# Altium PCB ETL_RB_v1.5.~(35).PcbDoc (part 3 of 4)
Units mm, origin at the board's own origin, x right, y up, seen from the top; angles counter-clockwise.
Board outline 130.3 x 56.5 mm, 8 copper layers (Top Layer, plane 1, M1, plane 2, plane 3, M2, plane 4, Bottom Layer), stack 0.937 mm thick; 212 components, 186 nets, 1961 pads, 953 vias.
Unrouted connection lines stored in the file: 395.

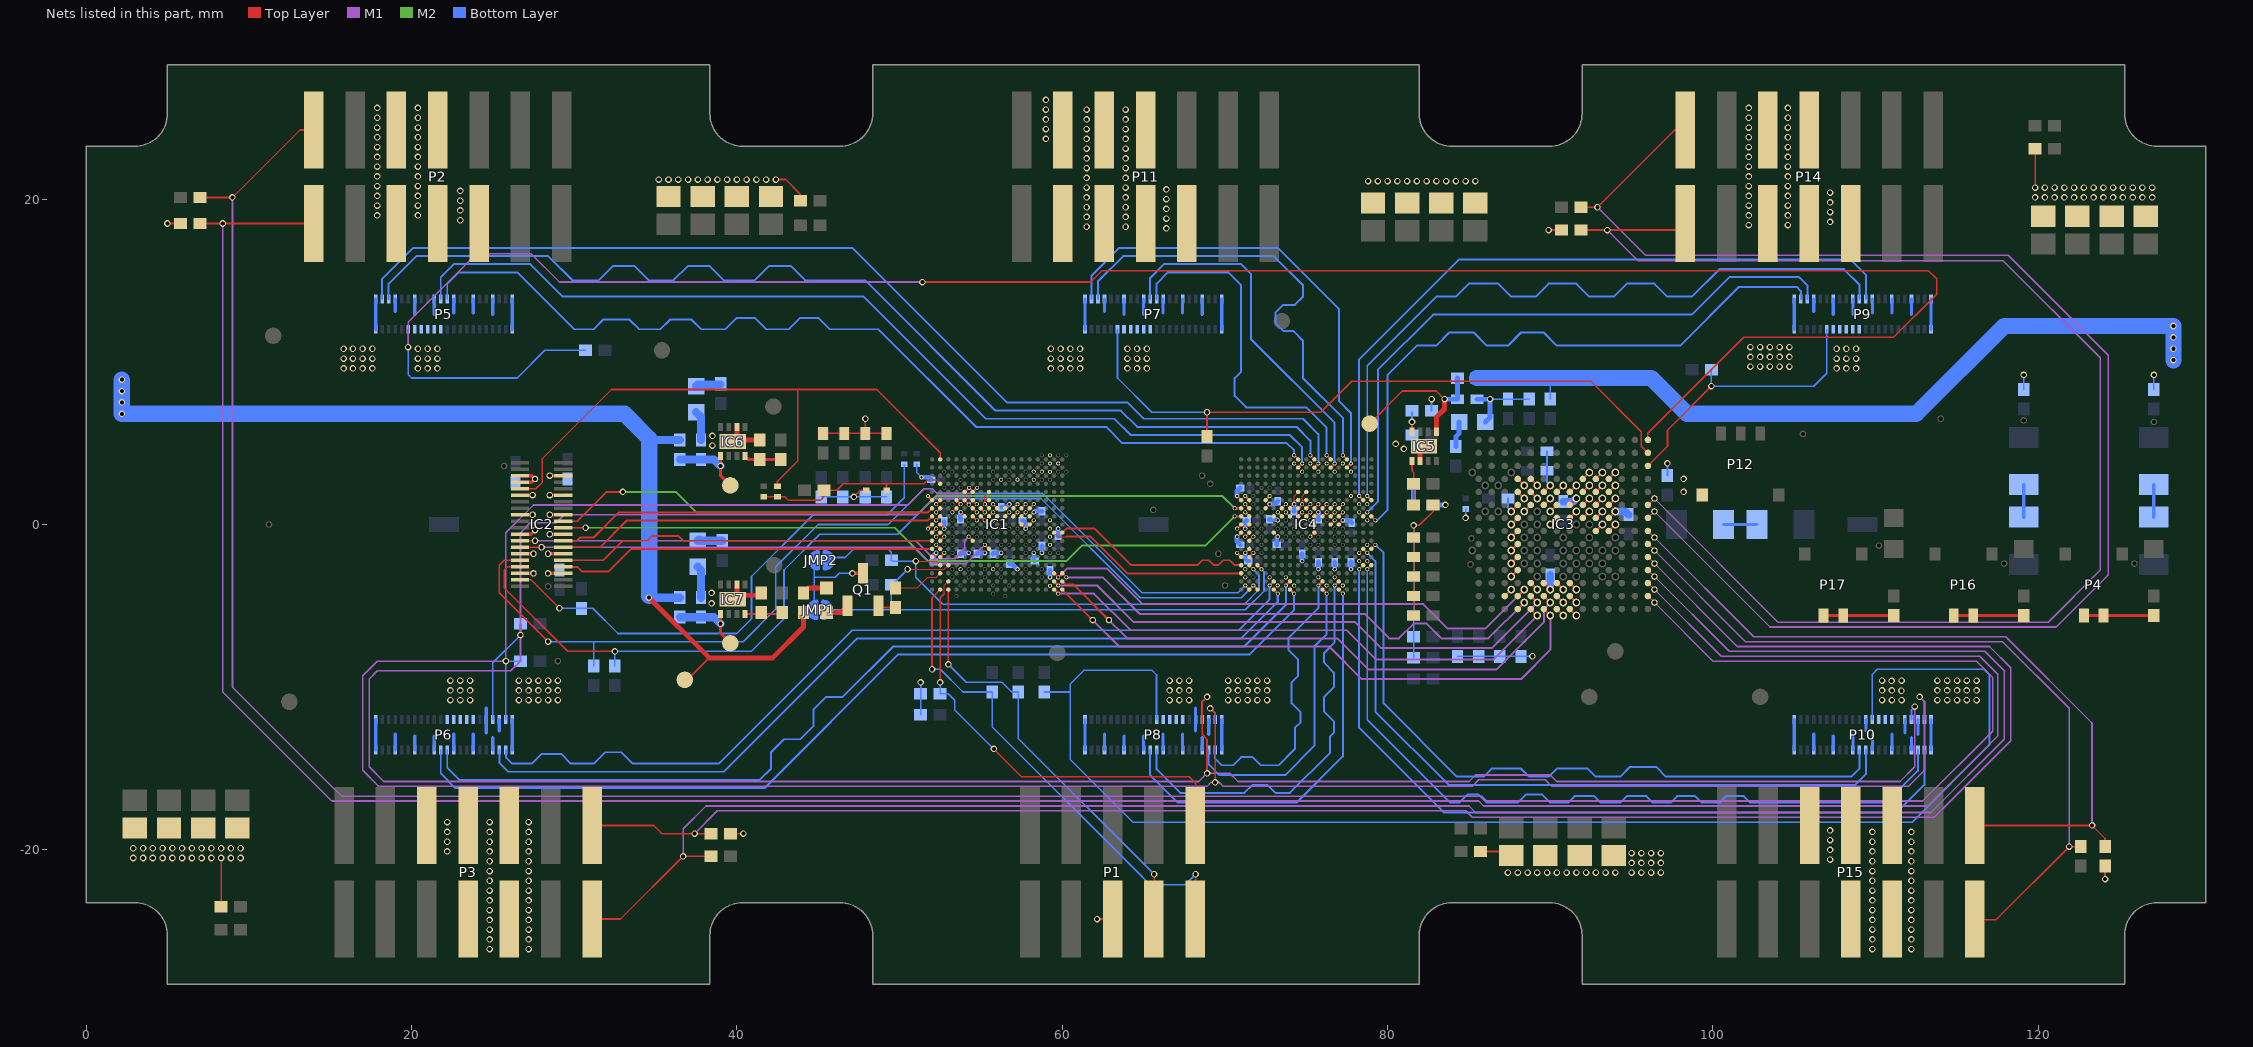
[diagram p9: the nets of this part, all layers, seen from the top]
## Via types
v1: diameter 0.4, hole 0.25, Top Layer to Bottom Layer, 953 vias

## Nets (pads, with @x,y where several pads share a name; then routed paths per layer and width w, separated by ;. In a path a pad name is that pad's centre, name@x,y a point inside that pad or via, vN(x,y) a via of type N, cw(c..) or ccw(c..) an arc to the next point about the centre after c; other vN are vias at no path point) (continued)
GND: C105.2 C106.2 C107.2 C108.2 C109.2 C111.2 C112.2 C113.2 C114.2 C115.2 C116.2 C117.2 C118.2 C119.2 C120.2 C121.2 C122.2 C123.2 C124.2 C125.2 C126.2 C127.2 C128.2 C129.2 C130.2 C131.2 C132.2 C133.2 C134.2 C135.2 C136.2 C138.2 C139.2 C140.2 C141.2 C150.2 C151.2 C152.2 C153.2 C154.2 C155.2 C160.2 C162.2 C163.2 C164.2 C165.2 C166.2 C167.2 C168.2 C169.2 C201.1 C202.1 C203.1 C204.1 C205.1 C206.1 C207.1 C208.1 C209.1 C210.1 C211.1 C212.1 C213.1 C214.1 C218.2 C219.2 C220.2 C221.2 C222.2 C223.2 C224.2 C225.2 C226.2 C227.2 C228.2 C229.2 C230.2 C231.2 C232.2 C233.2 IC1.E8 IC1.F1 IC1.F2 IC1.F4 IC1.F8 IC1.G2 IC1.G4 IC1.G6 IC1.G7 IC1.G8 IC1.G9 IC1.G10 IC1.G11 IC1.G12 IC1.G13 IC1.H2 IC1.H5 IC1.H6 IC1.H7 IC1.H8 IC1.H9 IC1.H10 IC1.H11 IC1.H12 IC1.H13 IC1.J1 IC1.J2 IC1.J12 IC1.J13 IC1.K1 IC1.K2 IC1.L2 IC1.M2 IC1.N1 IC1.N2 IC2.5 IC2.6 IC2.11 IC2.12 IC2.17 IC2.18 IC2.23 IC2.24 IC2.29 IC2.30 IC2.34 IC2.35 IC2.36 IC3.D4 IC3.D5 IC3.D6 IC3.D7 IC3.D8 IC3.E4 IC3.E5 IC3.E6 IC3.E7 IC3.E8 IC3.F4 IC3.F5 IC3.F6 IC3.F7 IC3.G5 IC3.G6 IC3.G7 IC3.G12 IC3.G13 IC3.G14 IC3.H5 IC3.H6 IC3.H7 IC3.H12 IC3.H13 IC3.H14 IC3.J5 IC3.J6 IC3.J12 IC3.K4 IC3.K5 IC3.K6 IC3.K12 IC3.L4 IC3.L5 IC3.L6 IC3.L7 IC3.L8 IC3.L9 IC3.L10 IC3.L11 IC3.M13 IC4.E8 IC4.E9 IC4.F1 IC4.F2 IC4.F4 IC4.F8 IC4.F9 IC4.G2 IC4.G4 IC4.G6 IC4.G7 IC4.G8 IC4.G9 IC4.G10 IC4.G11 IC4.G12 IC4.G13 IC4.H2 IC4.H5 IC4.H6 IC4.H7 IC4.H8 IC4.H9 IC4.H10 IC4.H11 IC4.H12 IC4.H13 IC4.J1 IC4.J2 IC4.J10 IC4.J12 IC4.J13 IC4.K1 IC4.K2 IC4.K5 IC4.K10 IC4.L2 IC4.M2 IC4.N1 IC4.N2 IC5.6 IC5.9 IC6.6 IC6.9 IC7.6 IC7.9 JMP1.1 JMP2.1 P1.6 P2.5 P2.6 P2.7 P2.8 P2.9 P3.5 P3.6 P3.7 P3.8 P3.9 P5.11 P5.12 P5.13 P5.14 P5.15 P5.23 P5.26 P5.29 P5.32 P5.35 P5.38 P5.41 P5.42 P5.43 P5.44 P6.11 P6.12 P6.13 P6.14 P6.15 P6.17 P6.19 P6.23 P6.26 P6.29 P6.32 P6.35 P6.38 P6.41 P6.42 P6.43 P6.44 P7.11 P7.12 P7.13 P7.14 P7.15 P7.23 P7.26 P7.29 P7.32 P7.35 P7.38 P7.41 P7.42 P7.43 P7.44 P8.12 P8.13 P8.14 P8.15 P8.17 P8.19 P8.23 P8.26 P8.29 P8.32 P8.35 P8.38 P8.41 P8.42 P8.43 P8.44 P9.11 P9.12 P9.13 P9.14 P9.15 P9.23 P9.26 P9.29 P9.32 P9.35 P9.38 P9.41 P9.42 P9.43 P9.44 P10.11 P10.13 P10.14 P10.15 P10.17 P10.19 P10.23 P10.26 P10.29 P10.32 P10.35 P10.38 P10.41 P10.42 P10.43 P10.44 P11.5 P11.6 P11.7 P11.8 P11.9 P12.4 P14.5 P14.6 P14.7 P14.8 P14.9 P15.5 P15.6 P15.7 P15.8 P15.9 pad.1@27.5,-1.8 pad.1@27.5,-3 pad.1@27.6,2.8 pad.1@27.6,-0.35 pad.1@27.45,0.6 pad.1@27.45,1.8 pad.1@28.4,-1.8 pad.1@28.4,-3 pad.1@28.5,0.6 pad.1@28.5,1.8 pad.1@28.5,3 pad.1@28.5,-0.6 pad.1@51.35,2.9 pad.1@51.75,1.75 pad.1@51.75,-0.25 pad.1@52.25,0.25 pad.1@52.25,0.75 pad.1@52.25,1.25 pad.1@52.25,-0.25 pad.1@52.25,-0.75 pad.1@52.25,-1.25 pad.1@52.25,-1.75 pad.1@52.75,-0.25 pad.1@52.75,-0.75 pad.1@52.75,-1.75 pad.1@53.25,0.75 pad.1@53.75,0.75 pad.1@53.75,1.25 pad.1@53.75,-2.75 pad.1@54.25,-1.75 pad.1@54.75,0.25 pad.1@54.75,0.75 pad.1@55.25,0.25 pad.1@55.25,0.75 pad.1@55.25,1.25 pad.1@55.25,-1.75 pad.1@55.75,0.25 pad.1@55.75,0.75 pad.1@55.75,1.25 pad.1@55.75,-2.75 pad.1@56.25,2.75 pad.1@56.25,-1.75 pad.1@56.75,0.75 pad.1@56.75,1.25 pad.1@57.25,0.75 pad.1@57.25,1.25 pad.1@57.25,2.75 pad.1@57.25,-2.75 pad.1@57.75,0.75 pad.1@57.75,1.25 pad.1@57.75,-0.25 pad.1@58.25,0.25 pad.1@58.25,0.75 pad.1@58.25,1.25 pad.1@58.25,2.75 pad.1@58.25,3.25 pad.1@58.25,-1.75 pad.1@58.75,3.25 pad.1@58.75,-1.75 pad.1@59.25,0.25 pad.1@59.25,3.75 pad.1@59.25,4.25 pad.1@59.25,-0.25 pad.1@59.25,-0.75 pad.1@59.25,-1.25 pad.1@59.25,-3.25 pad.1@59.75,3.75 pad.1@59.75,-0.25 pad.1@59.248,3.238 pad.1@59.248,-3.771 pad.1@70.75,1.75 pad.1@70.75,-0.25 pad.1@70.75,-0.75 pad.1@70.75,-1.75 pad.1@71.25,0.75 pad.1@71.25,1.25 pad.1@71.25,1.75 pad.1@71.25,-0.25 pad.1@71.25,-0.75 pad.1@71.25,-1.75 pad.1@71.25,-2.75 pad.1@71.25,-3.25 pad.1@71.75,-0.75 pad.1@71.75,-1.75 pad.1@72.75,1.25 pad.1@72.75,1.75 pad.1@72.75,-3.25 pad.1@73.25,0.25 pad.1@73.25,0.75 pad.1@73.25,-0.75 pad.1@73.25,-3.75 pad.1@73.75,0.75 pad.1@73.75,1.25 pad.1@73.75,-3.25 pad.1@74.25,1.25 pad.1@74.25,3.75 pad.1@74.75,0.75 pad.1@74.75,1.25 pad.1@74.75,3.25 pad.1@74.75,-2.25 pad.1@74.255,-3.755 pad.1@75.25,0.25 pad.1@75.25,0.75 pad.1@75.25,1.25 pad.1@75.25,3.75 pad.1@75.25,-0.75 pad.1@75.75,0.75 pad.1@75.75,1.25 pad.1@75.75,3.25 pad.1@75.75,-2.75 pad.1@75.75,-3.25 pad.1@76.25,0.75 pad.1@76.25,1.25 pad.1@76.25,3.75 pad.1@76.25,-3.75 pad.1@76.75,0.25 pad.1@76.75,0.75 pad.1@76.75,1.25 pad.1@76.75,3.25 pad.1@76.75,-2.75 pad.1@76.75,-3.25 pad.1@77.25,0.25 pad.1@77.25,0.75 pad.1@77.25,1.25 pad.1@77.25,3.75 pad.1@77.25,-3.75 pad.1@77.75,1.75 pad.1@77.75,3.25 pad.1@77.75,-2.75 pad.1@78.25,0.75 pad.1@78.25,1.25 pad.1@78.25,-1.75 pad.1@78.25,-2.25 pad.1@78.75,0.25 pad.1@78.75,1.25 pad.1@78.75,-1.25 pad.1@78.75,-2.25 pad.1@87.6,0 pad.1@87.6,0.8 pad.1@87.6,-0.8 pad.1@87.6,-1.6 pad.1@87.6,-2.4 pad.1@87.6,-3.2 pad.1@87.6,-4 pad.1@88.4,0.8 pad.1@88.4,1.6 pad.1@88.4,2.4 pad.1@89.2,1.6 pad.1@89.2,2.4 pad.1@89.2,-4 pad.1@90,0 pad.1@90,0.8 pad.1@90,1.6 pad.1@90,2.4 pad.1@90,-4 pad.1@90.8,2.4 pad.1@90.8,-4 pad.1@90.8,-4.8 pad.1@90.8,-5.6 pad.1@91.6,0.8 pad.1@91.6,1.6 pad.1@91.6,2.4 pad.1@91.6,-4 pad.1@91.6,-4.8 pad.1@91.6,-5.6 pad.1@92.4,0.8 pad.1@92.4,1.6 pad.1@92.4,2.4 pad.1@92.4,3.2 pad.1@93.2,0 pad.1@93.2,0.8 pad.1@93.2,1.6 pad.1@93.2,2.4 pad.1@93.2,3.2 pad.1@94,0 pad.1@94,0.8 pad.1@94,1.6 pad.1@94,2.4 pad.1@94,3.2 pad.1@119.1,9.2 pad.1@127.1,9.2 Q1.3 R112.2 R115.2 R118.1 R120.1 R122.1 R123.2 R126.2 R132.2 R134.1 R143.1 R146.1 R203.1 R205.1 R207.1 R209.1 R211.1 R213.1 R215.1 R217.1 R219.1 R221.1 R223.1 R225.1 R227.1 R229.1 R233.2 R234.2 R235.2 R236.2 RT1.1 RT2.1 | length 216
  Top Layer w0.076: pad.1@55.25,1.25 55.25,1.5 ; IC1.F8@55.5,1.5 55.25,1.5 ; IC1.E8@55.5,2 55.25,1.75 55.25,1.5 ; pad.1@74.25,1.25 74.25,1.5 ; IC4.F8@74.5,1.5 74.25,1.5 ; IC4.E8@74.5,2 74.25,1.75 74.25,1.5 ; pad.1@74.75,1.25 74.75,1.5 ; IC4.F9@75,1.5 74.75,1.5 ; IC4.E9@75,2 74.75,1.75 74.75,1.5
  Top Layer w0.102: v1(5,18.5) R233.2@5.8,18.5 ; R217.1@8.3,-23.5 8.3,-20.8 ; R234.2@39.6,-19 v1(40.4,-19) ; v1(42.4,21.2) 43,21.2 43.9,20.3 R215.1@43.9,19.9 ; C151.2@45.3,5.6 C150.2@46.6,5.6 C109.2@47.9,5.6 ; v1(47.2,1.7) 47.6,2.1 RT1.1@47.95,2.1 ; v1(47.9,6.5) C109.2@47.9,5.6 ; C141.2@49.2,5.6 C109.2@47.9,5.6 ; v1@62.2,-24.25 v1(62.15,-24.25) P1.6@63.1,-24.25 ; C201.1@81.6,-5.6 C203.1@81.6,-4.4 C205.1@81.6,-3.2 C207.1@81.6,-2 C210.1@81.6,-0.8 v1(81.6,-0.05) 81.95,-0.05 82.8,0.8 R112.2@82.8,1.2 ; R221.1@85.7,-20.1 87.35,-20.1 C233.2@87.6,-20.35 ; v1(89.9,18.1) R235.2@90.7,18.1 ; v1(119.8,20.7) R219.1@119.8,23.1 ; v1(124.1,-21.8) R236.2@124.1,-21
  Top Layer w0.13: pad.1@51.75,-0.25 IC1.J1@52,0 ; pad.1@51.75,1.75 IC1.F1@52,1.5 ; IC1.N1@52,-2 pad.1@52.25,-1.75 ; IC1.K1@52,-0.5 pad.1@52.25,-0.25 ; pad.1@52.25,-1.25 IC1.M2@52.5,-1.5 ; pad.1@52.25,-0.75 IC1.K2@52.5,-0.5 ; pad.1@52.25,0.25 IC1.H2@52.5,0.5 ; pad.1@52.25,0.75 IC1.G2@52.5,1 ; pad.1@52.25,1.25 IC1.F2@52.5,1.5 ; IC1.N2@52.5,-2 pad.1@52.75,-1.75 ; IC1.L2@52.5,-1 pad.1@52.75,-0.75 ; IC1.J2@52.5,0 pad.1@52.75,-0.25 ; pad.1@53.25,0.75 IC1.G4@53.5,1 ; IC1.F4@53.5,1.5 pad.1@53.75,1.25 ; pad.1@53.75,0.75 IC1.H5@54,0.5 ; IC1.H6@54.5,0.5 pad.1@54.75,0.25 ; IC1.G6@54.5,1 pad.1@54.75,0.75 ; IC1.H7@55,0.5 pad.1@55.25,0.25 ; IC1.G7@55,1 pad.1@55.25,0.75 ; pad.1@55.25,1.25 IC1.G8@55.5,1 ; IC1.H8@55.5,0.5 pad.1@55.75,0.75 ; pad.1@55.75,0.25 IC1.H9@56,0.5 ; pad.1@55.75,1.25 IC1.G9@56,1 ; IC1.H10@56.5,0.5 pad.1@56.75,0.75 ; IC1.G10@56.5,1 pad.1@56.75,1.25 ; IC1.H11@57,0.5 pad.1@57.25,0.75 ; IC1.G11@57,1 pad.1@57.25,1.25 ; IC1.J12@57.5,0 pad.1@57.75,-0.25 ; IC1.H12@57.5,0.5 pad.1@57.75,0.75 ; IC1.G12@57.5,1 pad.1@57.75,1.25 ; IC1.J13@58,0 pad.1@58.25,0.25 ; IC1.H13@58,0.5 pad.1@58.25,0.75 ; IC1.G13@58,1 pad.1@58.25,1.25 ; pad.1@70.75,-1.75 IC4.N1@71,-2 ; pad.1@70.75,-0.75 IC4.K1@71,-0.5 ; pad.1@70.75,-0.25 IC4.J1@71,0 ; pad.1@70.75,1.75 IC4.F1@71,1.5 ; pad.1@71.25,-1.75 IC4.M2@71.5,-1.5 ; pad.1@71.25,-0.75 IC4.K2@71.5,-0.5 ; pad.1@71.25,-0.25 IC4.J2@71.5,0 ; pad.1@71.25,0.75 IC4.H2@71.5,0.5 ; pad.1@71.25,1.25 IC4.G2@71.5,1 ; pad.1@71.25,1.75 IC4.F2@71.5,1.5 ; IC4.N2@71.5,-2 pad.1@71.75,-1.75 ; IC4.L2@71.5,-1 pad.1@71.75,-0.75 ; IC4.G4@72.5,1 pad.1@72.75,1.25 ; IC4.F4@72.5,1.5 pad.1@72.75,1.75 ; IC4.K5@73,-0.5 pad.1@73.25,-0.75 ; IC4.H5@73,0.5 pad.1@73.25,0.25 ; pad.1@73.25,0.75 IC4.H6@73.5,0.5 ; IC4.G6@73.5,1 pad.1@73.75,1.25 ; pad.1@73.75,0.75 IC4.H7@74,0.5 ; IC4.G7@74,1 pad.1@74.25,1.25 ; IC4.H8@74.5,0.5 pad.1@74.75,0.75 ; IC4.G8@74.5,1 pad.1@74.75,1.25 ; IC4.H9@75,0.5 pad.1@75.25,0.75 ; IC4.G9@75,1 pad.1@75.25,1.25 ; pad.1@75.25,-0.75 IC4.K10@75.5,-0.5 ; pad.1@75.25,0.25 IC4.J10@75.5,0 ; IC4.H10@75.5,0.5 pad.1@75.75,0.75 ; IC4.G10@75.5,1 pad.1@75.75,1.25 ; IC4.H11@76,0.5 pad.1@76.25,0.75 ; IC4.G11@76,1 pad.1@76.25,1.25 ; IC4.J12@76.5,0 pad.1@76.75,0.25 ; IC4.H12@76.5,0.5 pad.1@76.75,0.75 ; IC4.G12@76.5,1 pad.1@76.75,1.25 ; IC4.J13@77,0 pad.1@77.25,0.25 ; IC4.H13@77,0.5 pad.1@77.25,0.75 ; IC4.G13@77,1 pad.1@77.25,1.25 ; IC3.M13@87.2,-4.4 pad.1@87.6,-4 ; pad.1@87.6,-3.2 IC3.L11@88,-2.8 ; pad.1@87.6,-2.4 IC3.L10@88,-2 ; pad.1@87.6,-1.6 IC3.L9@88,-1.2 ; pad.1@87.6,-0.8 IC3.L8@88,-0.4 ; pad.1@87.6,0 IC3.L7@88,0.4 ; pad.1@87.6,0.8 IC3.L6@88,1.2 ; IC3.L5@88,2 pad.1@88.4,1.6 ; IC3.L4@88,2.8 pad.1@88.4,2.4 ; pad.1@88.4,0.8 IC3.K6@88.8,1.2 ; IC3.K12@88.8,-3.6 pad.1@89.2,-4 ; IC3.K5@88.8,2 pad.1@89.2,1.6 ; IC3.K4@88.8,2.8 pad.1@89.2,2.4 ; IC3.J12@89.6,-3.6 pad.1@90,-4 ; IC3.J6@89.6,1.2 pad.1@90,1.6 ; IC3.J5@89.6,2 pad.1@90,2.4 ; pad.1@90,0 IC3.H7@90.4,0.4 ; pad.1@90,0.8 IC3.H6@90.4,1.2 ; IC3.H14@90.4,-5.2 pad.1@90.8,-5.6 ; IC3.H13@90.4,-4.4 pad.1@90.8,-4.8 ; IC3.H12@90.4,-3.6 pad.1@90.8,-4 ; IC3.H5@90.4,2 pad.1@90.8,2.4 ; IC3.G14@91.2,-5.2 pad.1@91.6,-5.6 ; IC3.G13@91.2,-4.4 pad.1@91.6,-4.8 ; IC3.G12@91.2,-3.6 pad.1@91.6,-4 ; IC3.G7@91.2,0.4 pad.1@91.6,0.8 ; IC3.G6@91.2,1.2 pad.1@91.6,1.6 ; IC3.G5@91.2,2 pad.1@91.6,2.4 ; IC3.F7@92,0.4 pad.1@92.4,0.8 ; IC3.F6@92,1.2 pad.1@92.4,1.6 ; IC3.F5@92,2 pad.1@92.4,2.4 ; IC3.F4@92,2.8 pad.1@92.4,3.2 ; IC3.E8@92.8,-0.4 pad.1@93.2,0 ; IC3.E7@92.8,0.4 pad.1@93.2,0.8 ; IC3.E6@92.8,1.2 pad.1@93.2,1.6 ; IC3.E5@92.8,2 pad.1@93.2,2.4 ; IC3.E4@92.8,2.8 pad.1@93.2,3.2 ; IC3.D8@93.6,-0.4 pad.1@94,0 ; IC3.D7@93.6,0.4 pad.1@94,0.8 ; IC3.D6@93.6,1.2 pad.1@94,1.6 ; IC3.D5@93.6,2 pad.1@94,2.4 ; IC3.D4@93.6,2.8 pad.1@94,3.2
  Top Layer w0.2: IC2.6@26.67,-3 pad.1@27.5,-3 ; IC2.12@26.67,-1.8 pad.1@27.5,-1.8 ; IC2.18@26.67,-0.6 27.35,-0.6 pad.1@27.6,-0.35 ; IC2.24@26.67,0.6 pad.1@27.45,0.6 ; IC2.30@26.67,1.8 pad.1@27.45,1.8 ; IC2.34@26.67,2.6 27.4,2.6 pad.1@27.6,2.8 27.4,3 IC2.36@26.67,3 ; pad.1@28.4,-3 IC2.5@29.33,-3 ; pad.1@28.4,-1.8 IC2.11@29.33,-1.8 ; pad.1@28.5,-0.6 IC2.17@29.33,-0.6 ; pad.1@28.5,0.6 IC2.23@29.33,0.6 ; pad.1@28.5,1.8 IC2.29@29.33,1.8 ; pad.1@28.5,3 IC2.35@29.33,3 ; v1(47.1,-3) Q1.3@47.75,-3
  Top Layer w0.3: IC7.9@39.75,-4.6 IC7.9@40,-4.35 ; IC7.6@40,-3.7 IC7.9@40,-4.35 ; IC6.6@40,6 40,5.35 39.875,5.225 39.9,5.2 R115.2@41.4,5.2 ; R123.2@41.5,-4.2 41.55,-4.2 41.4,-4.35 IC7.9@40,-4.35 ; IC5.6@82,3.9 82,4.55 IC5.9@82.25,4.8
  Bottom Layer w0.102: 44.75,-2.366 44.75,-2.45 44.75,-2.633 44.75,-3.25 ; 44.9,-4.95 44.75,-4.8 44.75,-4.773 44.75,-3.25 ; R122.1@45.2,1.7 R120.1@46.5,1.7 v1(47.2,1.7) R134.1@49.2,1.7 ; v1(47.1,-3) 46.3,-3 46.05,-3.25 44.75,-3.25 ; R146.1@51.05,3.7 51.05,3.2 pad.1@51.35,2.9 ; R132.2@51.3,-11.7 v1(51.3,-9.7) ; R203.1@81.6,-8.2 R205.1@81.6,-6.9 C202.1@81.6,-5.6 C204.1@81.6,-4.4 C206.1@81.6,-3.2 C209.1@81.6,-2 C208.1@81.6,-0.8 v1(81.6,-0.05) ; R126.2@82.7,7 v1(82.7,7.7) ; R207.1@84.3,-8.1 R209.1@85.6,-8.1 R211.1@86.9,-8.1 R213.1@88.2,-8.1 v1(88.9,-8.1) ; v1(84.8,0.4) RT2.1@84.8,0.95 ; v1(86.3,7.7) C214.1@87.4,7.7 R229.1@88.7,7.7 ; C211.1@87.4,1.6 87.4,1 pad.1@87.6,0.8 ; C213.1@89.8,4.5 C212.1@89.8,3.3 89.8,2.6 pad.1@90,2.4 ; R227.1@97.2,3 v1(97.2,3.75) ; R225.1@119.1,8.3 pad.1@119.1,9.2 ; R223.1@127.1,8.3 pad.1@127.1,9.2
  Bottom Layer w0.2: P6.44@17.8,-13.85 P6.41@17.8,-12 ; P5.42@17.8,12 P5.43@17.8,13.85 ; P6.38@19,-13.85 19,-12.9 ; 19,13.1 P5.23@19,13.85 ; P6.35@20.2,-13.85 20.2,-13 ; 20.2,12.9 P5.26@20.2,13.85 ; P6.32@21.4,-13.85 21.4,-13 ; 21.4,12.9 P5.29@21.4,13.85 ; P6.29@22.6,-13.85 22.6,-12.9 ; 22.6,13 P5.32@22.6,13.85 ; P6.26@23.8,-13.85 23.8,-12.9 ; 23.8,13 P5.35@23.8,13.85 ; 24.6,-12.8 P6.17@24.6,-12 24.6,-11.3 ; P6.23@25,-13.85 25,-13.1 ; 25,12.9 P5.38@25,13.85 ; 25.4,-12.7 P6.19@25.4,-12 ; P6.43@26.2,-13.85 P6.42@26.2,-12 ; P5.41@26.2,12 P5.44@26.2,13.85 ; P8.44@61.4,-13.85 P8.41@61.4,-12 ; P7.42@61.4,12 P7.43@61.4,13.85 ; P8.38@62.6,-13.85 62.6,-12.9 ; 62.6,13.1 P7.23@62.6,13.85 ; P8.35@63.8,-13.85 63.8,-13 ; 63.8,12.9 P7.26@63.8,13.85 ; P8.32@65,-13.85 65,-13 ; 65,12.9 P7.29@65,13.85 ; P8.29@66.2,-13.85 66.2,-12.9 ; 66.2,13 P7.32@66.2,13.85 ; P8.26@67.4,-13.85 67.4,-12.9 ; 67.4,13 P7.35@67.4,13.85 ; 68.2,-12.7 P8.17@68.2,-12 68.2,-11.3 ; P8.23@68.6,-13.85 68.6,-13.1 ; 68.6,12.9 P7.38@68.6,13.85 ; 69,-12.9 P8.19@69,-12 ; P8.43@69.8,-13.85 P8.42@69.8,-12 ; P7.41@69.8,12 P7.44@69.8,13.85 ; P10.44@105,-13.85 P10.41@105,-12 ; P9.42@105,12 P9.43@105,13.85 ; P10.38@106.2,-13.85 106.2,-12.9 ; 106.2,13.1 P9.23@106.2,13.85 ; P10.35@107.4,-13.85 107.4,-13 ; 107.4,12.9 P9.26@107.4,13.85 ; P10.32@108.6,-13.85 108.6,-13 ; 108.6,12.9 P9.29@108.6,13.85 ; 109.4,-12.7 P10.11@109.4,-12 ; P10.29@109.8,-13.85 109.8,-12.9 ; 109.8,13 P9.32@109.8,13.85 ; P10.26@111,-13.85 111,-12.9 ; 111,13 P9.35@111,13.85 ; 111.8,-12.8 P10.17@111.8,-12 ; P10.23@112.2,-13.85 112.2,-13.1 ; 112.2,12.9 P9.38@112.2,13.85 ; 112.6,-12.9 P10.19@112.6,-12 ; P10.43@113.4,-13.85 P10.42@113.4,-12 ; P9.41@113.4,12 P9.44@113.4,13.85
  Bottom Layer w0.3: pad.1@51.35,2.9 51.79,2.9 C119.2@51.94,2.75 C119.2@51.85,2.75 ; C125.2@52.09,-2.3 52.09,-1.91 pad.1@52.25,-1.75 ; pad.1@52.75,-0.25 C116.2@52.75,0.19 ; C117.2@53.75,-1.81 53.81,-1.75 pad.1@54.25,-1.75 ; C126.2@53.75,0.31 pad.1@53.75,0.75 ; C114.2@54.75,-1.81 54.81,-1.75 pad.1@55.25,-1.75 ; C122.2@55.75,-1.81 55.81,-1.75 pad.1@56.25,-1.75 ; C120.2@56.25,1.06 56.56,1.06 pad.1@56.75,1.25 ; C118.2@56.75,-2.41 56.91,-2.41 pad.1@57.25,-2.75 ; C136.2@57.56,0.25 57.75,0.06 pad.1@57.75,-0.25 ; pad.1@58.25,-1.75 58.25,-2.19 C123.2@58.31,-2.25 ; pad.1@58.25,0.75 58.31,0.81 C124.2@58.75,0.81 ; pad.1@58.75,-1.75 C115.2@58.75,-1.31 ; pad.1@59.25,-3.25 C121.2@59.25,-2.81 ; C113.2@59.75,-0.7 C113.2@59.75,-0.69 pad.1@59.75,-0.25 ; pad.1@70.75,-0.75 70.75,-1.06 C130.2@70.94,-1.25 ; pad.1@70.75,1.75 70.75,2.06 C133.2@70.94,2.25 ; pad.1@71.25,-1.75 71.25,-2.06 C132.2@71.44,-2.25 ; pad.1@71.25,-0.25 71.25,0.16 C164.2@71.34,0.25 ; C163.2@72.75,0.31 73.19,0.31 pad.1@73.25,0.25 ; pad.1@72.75,1.25 73.06,1.25 C167.2@73.25,1.44 ; C168.2@73.19,-1.25 73.19,-0.81 pad.1@73.25,-0.75 ; pad.1@74.25,1.25 C129.2@74.25,0.81 C129.2@74.26,0.8 ; pad.1@74.75,-2.25 C128.2@74.75,-1.81 ; pad.1@75.75,-2.75 C134.2@75.75,-2.31 ; C131.2@75.75,0.31 pad.1@75.75,0.75 ; pad.1@76.75,-2.75 C165.2@76.75,-2.31 ; pad.1@77.25,0.25 77.66,0.25 C166.2@77.8,0.11 ; pad.1@77.75,-2.75 C135.2@77.75,-2.31 ; C155.2@82.8,1.2 v1(83.55,1.2) ; C105.2@85.5,7.7 v1(86.3,7.7) 86.3,6.6 C107.2@86,6.3
  Bottom Layer w0.48: pad.1@90,-4 C138.2@90,-3.1 ; C140.2@90.8,1.4 91.4,1.4 pad.1@91.6,1.6 ; pad.1@94,0.8 94.6,0.8 C139.2@94.8,0.6
  Bottom Layer w0.5: C108.2@37.5,6.9 37.8,6.6 C106.2@37.8,5.2 ; C169.2@37.6,-2.6 37.8,-2.8 C152.2@37.8,-4.5
  other v1: 24.8,-26.1 27.2,-26.1 109.8,-26.1 112.2,-26.1 24.8,-25.5 27.2,-25.5 109.8,-25.5 112.2,-25.5 24.8,-24.9 27.2,-24.9 109.8,-24.9 112.2,-24.9 24.8,-24.3 27.2,-24.3 109.8,-24.3 112.2,-24.3 24.8,-23.7 27.2,-23.7 109.8,-23.7 112.2,-23.7 24.8,-23.1 27.2,-23.1 109.8,-23.1 112.2,-23.1 24.8,-22.5 27.2,-22.5 109.8,-22.5 112.2,-22.5 24.8,-21.9 27.2,-21.9 109.8,-21.9 112.2,-21.9 87.4,-21.4 88,-21.4 88.6,-21.4 89.2,-21.4 89.8,-21.4 90.4,-21.4 91,-21.4 91.6,-21.4 92.2,-21.4 92.8,-21.4 93.4,-21.4 94,-21.4 95,-21.4 95.6,-21.4 96.2,-21.4 96.8,-21.4 24.8,-21.3 27.2,-21.3 109.8,-21.3 112.2,-21.3 95,-20.8 95.6,-20.8 96.2,-20.8 96.8,-20.8 24.8,-20.7 27.2,-20.7 109.8,-20.7 112.2,-20.7 107.2,-20.6 2.9,-20.5 3.5,-20.5 4.1,-20.5 4.7,-20.5 5.3,-20.5 5.9,-20.5 6.5,-20.5 7.1,-20.5 7.7,-20.5 8.3,-20.5 8.9,-20.5 9.5,-20.5 95,-20.2 95.6,-20.2 96.2,-20.2 96.8,-20.2 22.2,-20.1 24.8,-20.1 27.2,-20.1 109.8,-20.1 112.2,-20.1 107.2,-20 2.9,-19.9 3.5,-19.9 4.1,-19.9 4.7,-19.9 5.3,-19.9 5.9,-19.9 6.5,-19.9 7.1,-19.9 7.7,-19.9 8.3,-19.9 8.9,-19.9 9.5,-19.9 22.2,-19.5 24.8,-19.5 27.2,-19.5 109.8,-19.5 112.2,-19.5 107.2,-19.4 22.2,-18.9 24.8,-18.9 27.2,-18.9 109.8,-18.9 112.2,-18.9 107.2,-18.8 22.2,-18.3 24.8,-18.3 27.2,-18.3 22.4,-10.8 23,-10.8 23.6,-10.8 26.6,-10.8 27.2,-10.8 27.8,-10.8 28.4,-10.8 29,-10.8 66.6,-10.8 67.2,-10.8 67.8,-10.8 70.2,-10.8 70.8,-10.8 71.4,-10.8 72,-10.8 72.6,-10.8 110.4,-10.8 111,-10.8 111.6,-10.8 113.8,-10.8 114.4,-10.8 115,-10.8 115.6,-10.8 116.2,-10.8 111.581,-10.219 22.4,-10.2 23,-10.2 23.6,-10.2 26.6,-10.2 27.2,-10.2 27.8,-10.2 28.4,-10.2 29,-10.2 66.6,-10.2 67.2,-10.2 67.8,-10.2 70.2,-10.2 70.8,-10.2 71.4,-10.2 72,-10.2 72.6,-10.2 110.4,-10.2 111,-10.2 113.8,-10.2 114.4,-10.2 115,-10.2 115.6,-10.2 116.2,-10.2 22.4,-9.6 23,-9.6 23.6,-9.6 26.6,-9.6 27.2,-9.6 27.8,-9.6 28.4,-9.6 29,-9.6 66.6,-9.6 67.2,-9.6 67.8,-9.6 70.2,-9.6 70.8,-9.6 71.4,-9.6 72,-9.6 72.6,-9.6 110.4,-9.6 110.981,-9.619 111.6,-9.6 113.8,-9.6 114.4,-9.6 115,-9.6 115.6,-9.6 116.2,-9.6 38.45,-4.85 38.45,-4.2 98.2,2 98.2,2.8 81,4.65 38.5,4.85 80.5,4.95 38.5,5.45 15.827,9.6 16.4,9.6 17,9.6 17.6,9.6 20.4,9.6 21,9.6 21.6,9.6 59.3,9.6 59.9,9.6 60.5,9.6 61.1,9.6 64,9.6 64.6,9.6 65.2,9.6 107.6,9.6 108.2,9.6 108.8,9.6 102.3,9.7 102.9,9.7 103.5,9.7 104.1,9.7 104.7,9.7 15.827,10.2 16.4,10.2 17,10.2 17.6,10.2 20.4,10.2 21,10.2 21.6,10.2 59.3,10.2 59.9,10.2 60.5,10.2 61.1,10.2 64,10.2 64.6,10.2 65.2,10.2 107.6,10.2 108.2,10.2 108.8,10.2 102.3,10.3 102.9,10.3 103.5,10.3 104.1,10.3 104.7,10.3 15.827,10.8 16.4,10.8 17,10.8 17.6,10.8 20.4,10.8 21,10.8 21.6,10.8 59.3,10.8 59.9,10.8 60.5,10.8 61.1,10.8 64,10.8 64.6,10.8 65.2,10.8 107.6,10.8 108.2,10.8 108.8,10.8 102.3,10.9 102.9,10.9 103.5,10.9 104.1,10.9 104.7,10.9 66.4,18.2 61.5,18.3 63.9,18.3 102.2,18.4 104.6,18.4 107.2,18.6 23,18.7 66.4,18.8 61.5,18.9 63.9,18.9 17.9,19 20.4,19 102.2,19 104.6,19 107.2,19.2 23,19.3 66.4,19.4 61.5,19.5 63.9,19.5 17.9,19.6 20.4,19.6 102.2,19.6 104.6,19.6 107.2,19.8 23,19.9 66.4,20 61.5,20.1 63.9,20.1 119.8,20.1 120.4,20.1 121,20.1 121.6,20.1 122.2,20.1 122.8,20.1 123.4,20.1 124,20.1 124.6,20.1 125.2,20.1 125.8,20.1 126.4,20.1 127,20.1 17.9,20.2 20.4,20.2 102.2,20.2 104.6,20.2 107.2,20.4 23,20.5 66.4,20.6 61.5,20.7 63.9,20.7 120.4,20.7 121,20.7 121.6,20.7 122.2,20.7 122.8,20.7 123.4,20.7 124,20.7 124.6,20.7 125.2,20.7 125.8,20.7 126.4,20.7 127,20.7 17.9,20.8 20.4,20.8 102.2,20.8 104.6,20.8 78.8,21.1 79.4,21.1 80,21.1 80.6,21.1 81.2,21.1 81.8,21.1 82.4,21.1 83,21.1 83.6,21.1 84.2,21.1 84.8,21.1 85.4,21.1 35.2,21.2 35.8,21.2 36.4,21.2 37,21.2 37.6,21.2 38.2,21.2 38.8,21.2 39.4,21.2 40,21.2 40.6,21.2 41.2,21.2 41.8,21.2 61.5,21.3 63.9,21.3 17.9,21.4 20.4,21.4 102.2,21.4 104.6,21.4 61.5,21.9 63.9,21.9 17.9,22 20.4,22 102.2,22 104.6,22 61.5,22.5 63.9,22.5 17.9,22.6 20.4,22.6 102.2,22.6 104.6,22.6 61.5,23.1 63.9,23.1 17.9,23.2 20.4,23.2 102.2,23.2 104.6,23.2 61.5,23.7 63.9,23.7 17.9,23.8 20.4,23.8 102.2,23.8 104.6,23.8 61.5,24.3 63.9,24.3 17.9,24.4 20.4,24.4 102.2,24.4 104.6,24.4 61.5,24.9 63.9,24.9 17.9,25 20.4,25 102.2,25 104.6,25 61.5,25.5 63.9,25.5 17.9,25.6 20.4,25.6 102.2,25.6 104.6,25.6
I_1V5: C105.1 IC5.1 R129.2 TP15.1 | length 9.9
  Top Layer w0.102: TP15.1@78.9,6.2 80.9,8.2 83,8.2 v1(83.5,7.7)
  Top Layer w0.3: IC5.1@83,5.7 83,6.6 83.5,7.1 v1(83.5,7.7)
  Bottom Layer w0.3: v1(83.5,7.7) C105.1@84.3,7.7 R129.2@84.3,9
I_2V5RX: C152.1 IC7.1 R131.2 TP16.1 | length 4.7
  Top Layer w0.2: IC7.1@39,-5.5 v1(39,-6.1) 39,-6.7 TP16.1@39.6,-7.3
  Bottom Layer w0.5: R131.2@36.5,-5.7 38.6,-5.7 v1(39,-6.1)
I_2V5TX: C106.1 IC6.1 R130.2 TP17.1 | length 4.7
  Top Layer w0.2: IC6.1@39,4.2 v1(39,3.6) 39,3 TP17.1@39.6,2.4
  Bottom Layer w0.5: R130.2@36.5,4 38.6,4 v1(39,3.6)
IC1_SCL: IC1.U2 P1.2 R110.1 | length 31.1
  Top Layer w0.102: v1(52,-8.9) 52,-4.5 IC1.U2@52.5,-4 ; P1.2@68.18,-24.25 68.2,-24.23 v1(68.2,-21.5)
  Bottom Layer w0.102: v1(52,-8.9) 52.5,-8.9 53.9,-10.3 R110.1@55.7,-10.3 55.7,-12.45 64.45,-21.2 65.4,-22.15 67.55,-22.15 v1(68.2,-21.5)
IC1_SDA: IC1.U3 P1.4 R109.1 | length 27
  Top Layer w0.102: v1(53,-8.6) 53,-4.9 IC1.U3@53,-4 ; P1.4@65.64,-24.25 65.65,-24.24 v1(65.65,-21.5)
  Bottom Layer w0.102: v1(53,-8.6) 54.1,-9.7 56.3,-9.7 56.9,-10.3 R109.1@57.3,-10.3 57.3,-13.15 v1(65.65,-21.5)
LD_DIS: IC1.L6 IC2.16 pad.1@27.6,-1 pad.1@54.25,-0.75 | length 29.2
  Top Layer w0.102: IC2.16@26.67,-1 pad.1@27.6,-1
  Top Layer w0.13: pad.1@54.25,-0.75 IC1.L6@54.5,-1
  M1 w0.102: pad.1@27.6,-1 51,-1 52.1,-2.1 53.4,-2.1 54,-1.5 54,-1 pad.1@54.25,-0.75
LD_RSTN: IC1.M8 IC2.14 pad.1@28,-1.4 pad.1@55.25,-1.25 | length 29.8
  Top Layer w0.102: IC2.14@26.67,-1.4 pad.1@28,-1.4
  Top Layer w0.13: pad.1@55.25,-1.25 IC1.M8@55.5,-1.5
  M1 w0.102: pad.1@28,-1.4 50.9,-1.4 51.9,-2.4 54.1,-2.4 pad.1@55.25,-1.25
LV_RB: P11.3 P11.4 R129.1 R130.1 R131.1 R142.1 R228.2 TP5.1 | length 112.8
  Top Layer w0.102: TP5.1@36.8,-9.55 36.95,-9.55 38.3,-8.2
  Top Layer w0.3: v1(34.6,-4.5) 38.3,-8.2 42.2,-8.2 44.1,-6.3 R142.1@44.1,-5.4
  Bottom Layer w0.102: R228.2@90,7.7 90,9
  Bottom Layer w0.5: v1@34.625,-4.4 34.725,-4.5 R131.1@36.5,-4.5 ; 34.625,5.275 34.7,5.2 R130.1@36.5,5.2
  Bottom Layer w1: v1(2.2,8.9) v1(2.2,6.8) 33.1,6.8 34.625,5.275 v1@34.625,-4.4 ; R129.1@85.5,9 90,9 96.2,9 98.4,6.8 112.5,6.8 117.9,12.2 v1(128.3,12.2) v1(128.3,10.1)
  other v1: 2.2,7.5 2.2,8.2 128.3,10.8 128.3,11.5 59,23.7 59,24.3 59,24.9 59,25.5 59,26.1
M1SCL: IC1.E6 P6.20 P8.20 P10.20 pad.1@25.8,-8.4 pad.1@54.775,2.25 R103.1 | length 167.1
  Top Layer w0.102: v1(69.1,-11.3) 69.1,-11.313 69.4,-11.613 v1(69.4,-15.85)
  Top Layer w0.13: IC1.E6@54.5,2 54.75,2.25 pad.1@54.775,2.25
  M1 w0.102: pad.1@54.775,2.25 54.425,1.9 52.3,1.9 52,2.2 51.5,2.2 50.5,1.2 27.5,1.2 25.8,-0.5 pad.1@25.8,-8.4 17.9,-8.4 17,-9.3 17,-15.1 18,-16.1 68.9,-16.1 69.15,-15.85 69.65,-15.85 69.9,-16.1 85.2,-16.1 85.6,-15.7 89.7,-15.7 90.1,-16.1 112,-16.1 113,-15.1 113,-10.9 v1(112.7,-10.6)
  Bottom Layer w0.102: P6.20@25.8,-12 pad.1@25.8,-8.4 R103.1@26.7,-8.4 ; v1(69.1,-11.3) 69.4,-11.6 P8.20@69.4,-12 ; v1(112.7,-10.6) 113,-10.9 P10.20@113,-12
M1SDA: IC1.F6 P6.18 P8.18 P10.18 pad.1@26.7,-6.8 pad.1@54.75,1.25 R104.1 | length 166.6
  Top Layer w0.102: v1(68.9,-15.3) 68.9,-13.2 68.6,-12.9 68.6,-10.9 v1(68.9,-10.6)
  Top Layer w0.13: IC1.F6@54.5,1.5 pad.1@54.75,1.25
  M1 w0.102: pad.1@54.75,1.25 54.4,1.6 52.1,1.6 51.1,0.6 29.4,0.6 28.9,0.1 27.3,0.1 26.7,-0.5 pad.1@26.7,-6.8 26.7,-8.4 26.1,-9 17.9,-9 17.4,-9.5 17.4,-14.9 18.3,-15.8 68.4,-15.8 v1(68.9,-15.3) 70.3,-15.3 70.8,-15.8 85,-15.8 85.4,-15.4 90,-15.4 90.4,-15.8 111.5,-15.8 112.4,-14.9 v1(112.4,-11.2)
  Bottom Layer w0.102: P6.18@25,-12 25,-8.5 pad.1@26.7,-6.8 R104.1@26.7,-6.1 ; P8.18@68.6,-12 68.6,-10.9 v1(68.9,-10.6) ; P10.18@112.2,-12 112.2,-11.4 v1(112.4,-11.2)
M2SCL: IC1.E5 IC2.10 IC4.U2 pad.1@28.4,-7.2 pad.1@54.275,2.25 pad.1@71.25,-3.75 R105.1 | length 61
  Top Layer w0.102: IC2.10@26.67,-2.2 25.7,-2.2 25.4,-2.5 25.4,-4.2 pad.1@28.4,-7.2
  Top Layer w0.13: IC1.E5@54,2 54.25,2.25 pad.1@54.275,2.25 ; pad.1@71.25,-3.75 IC4.U2@71.5,-4
  Bottom Layer w0.102: pad.1@28.4,-7.2 31.2,-7.2 ; R105.1@31.2,-8.7 31.2,-7.2 ; pad.1@71.25,-3.75 70.8,-4.2 64.9,-4.2 58.8,1.9 54.625,1.9 pad.1@54.275,2.25 53.925,1.9 52.3,1.9 52,2.2 51.5,2.2 49.3,0 45,0 42.4,-2.6 42.4,-5.2 40.4,-7.2 31.2,-7.2
M2SDA: IC1.F5 IC2.8 IC4.U3 pad.1@54.251,1.226 pad.1@71.75,-3.75 R106.1 | length 60.2
  Top Layer w0.102: IC2.8@26.67,-2.6 25.9,-2.6 25.7,-2.8 25.7,-3.9 29.6,-7.8 v1(32.5,-7.8)
  Top Layer w0.13: IC1.F5@54,1.5 54.251,1.249 pad.1@54.251,1.226 ; pad.1@71.75,-3.75 IC4.U3@72,-4
  Bottom Layer w0.102: R106.1@32.5,-8.7 v1(32.5,-7.8) 40.9,-7.8 42.9,-5.8 42.9,-2.8 45.1,-0.6 49.9,-0.6 52.1,1.6 53.877,1.6 pad.1@54.251,1.226 54.625,1.6 58.7,1.6 64.8,-4.5 71,-4.5 pad.1@71.75,-3.75
NetC107_1: C107.1 R111.2 | length 1.6
  Bottom Layer w0.3: R111.2@84.2,4.8 84.2,5.4 84.4,5.6 C107.1@84.4,6.3
NetC108_1: C108.1 R114.1 | length 1.5
  Bottom Layer w0.5: C108.1@37.5,8.5 37.6,8.6 R114.1@39,8.6
NetC155_1: C155.1 R128.2 | length 1.3
  Bottom Layer w0.3: C155.1@81.6,1.2 R128.2@81.6,2.5
NetC169_1: C169.1 R125.1 | length 1.6
  Bottom Layer w0.5: C169.1@37.675,-0.925 C169.1@37.6,-1 R125.1@39.1,-1
NetD1_1: D1.1 R142.2 | length 1.8
  Top Layer w0.127: D1.1@45.3,-4.1 D1.1@45.5,-3.9
  Top Layer w0.3: R142.2@44.1,-4.2 44.4,-3.9 D1.1@45.5,-3.9
NetD1_2: D1.2 Q1.1 | length 1.5
  Top Layer w0.3: D1.2@45.5,-5.4 46.4,-5.4 Q1.1@46.8,-5
NetIC1_A2: IC1.A2 IC2.32 R144.1 | length 37.7
  Top Layer w0.102: IC2.32@26.67,2.2 27.65,2.2 28.05,2.6 28.05,4.05 32.3,8.3 43.75,8.3 ; R144.1@42.5,2.35 42.5,2.65 43.75,3.9 43.75,8.3 ; IC1.A2@52.5,4 52.5,4.4 48.6,8.3 43.75,8.3
NetIC1_G1: IC1.G1 IC2.15 | length 23.5
  Top Layer w0.12: IC2.15@29.33,-1 30.165,-1 30.365,-0.8 31.2,-0.8 32.75,0.75 51.75,0.75 IC1.G1@52,1
NetIC1_H1: IC1.H1 IC2.13 | length 23.5
  Top Layer w0.12: IC2.13@29.33,-1.4 31.6,-1.4 33.25,0.25 51.75,0.25 IC1.H1@52,0.5
NetIC1_L1: IC1.L1 IC2.9 | length 23.4
  Top Layer w0.12: IC2.9@29.33,-2.2 31.8,-2.2 33,-1 34.5,-1 34.8,-0.7 36.4,-0.7 36.7,-1 IC1.L1@52,-1
NetIC1_M1: IC1.M1 IC2.7 | length 23.4
  Top Layer w0.12: IC2.7@29.33,-2.6 30.2,-2.6 30.5,-2.9 32.1,-2.9 33.5,-1.5 IC1.M1@52,-1.5
NetIC1_P2: IC1.P2 IC4.P2 JMP2.2 pad.1@71.75,-2.75 R102.2 | length 32.7
  Top Layer w0.076: v1(51,-2.25) 52.25,-2.25 IC1.P2@52.5,-2.5
  Top Layer w0.13: IC4.P2@71.5,-2.5 pad.1@71.75,-2.75
  Bottom Layer w0.102: 45.65,-2.034 45.872,-2.034 46.666,-2.034 47.2,-1.5 49.3,-1.5 49.5,-1.7 R102.2@49.5,-2.2 49.55,-2.25 v1(51,-2.25) 51,-3.25 52.65,-4.9 71.2,-4.9 72.1,-4 72.1,-3.1 pad.1@71.75,-2.75
NetIC1_P3: IC1.P3 IC4.P3 JMP1.2 pad.1@72.25,-2.75 R101.1 | length 34.7
  Top Layer w0.076: v1(50.5,-2.75) 51.25,-2.75 52.75,-2.75 IC1.P3@53,-2.5
  Top Layer w0.13: IC4.P3@72,-2.5 pad.1@72.25,-2.75
  Bottom Layer w0.102: 45.55,-5.084 45.716,-5.25 49.5,-5.25 ; v1(50.5,-2.75) 49.55,-3.7 R101.1@49.5,-3.7 49.5,-5.25 ; pad.1@72.25,-2.75 72.4,-2.9 72.4,-4.1 71.25,-5.25 49.5,-5.25
NetIC1_R16: IC1.R16 IC3.L13 pad.1@59.75,-3.25 pad.1@88.4,-4 | length 32.3
  Top Layer w0.13: IC1.R16@59.5,-3 pad.1@59.75,-3.25 ; IC3.L13@88,-4.4 pad.1@88.4,-4
  M1 w0.12: pad.1@59.75,-3.25 60.3,-2.7 62.75,-2.7 64.95,-4.9 82.2,-4.9 83.7,-6.4 86,-6.4 pad.1@88.4,-4
NetIC1_R17: IC1.R17 IC3.L14 pad.1@60.25,-3.25 pad.1@88.4,-4.8 | length 32.3
  Top Layer w0.13: IC1.R17@60,-3 pad.1@60.25,-3.25 ; IC3.L14@88,-5.2 pad.1@88.4,-4.8
  M1 w0.12: pad.1@60.25,-3.25 62.5,-3.25 64.75,-5.5 78.6,-5.5 80.1,-7 80.7,-7 81.6,-6.1 82.4,-6.1 83.3,-7 86.2,-7 pad.1@88.4,-4.8
NetIC1_T16: IC1.T16 IC3.K13 pad.1@59.75,-3.75 pad.1@89.2,-4.8 | length 33.1
  Top Layer w0.13: IC1.T16@59.5,-3.5 pad.1@59.75,-3.75 ; IC3.K13@88.8,-4.4 pad.1@89.2,-4.8
  M1 w0.12: pad.1@59.75,-3.75 62.15,-3.75 64.4,-6 78,-6 79.6,-7.6 86.4,-7.6 pad.1@89.2,-4.8
NetIC1_T17: IC1.T17 IC3.J13 pad.1@62.875,-5.875 pad.1@90,-4.8 | length 35.7
  Top Layer w0.12: IC1.T17@60,-3.5 60.2,-3.7 60.7,-3.7 pad.1@62.875,-5.875
  Top Layer w0.13: IC3.J13@89.6,-4.4 pad.1@90,-4.8
  M1 w0.12: pad.1@62.875,-5.875 62.871,-5.875 62.625,-5.629 63.996,-7 76.9,-7 78.8,-8.9 86.7,-8.9 89.6,-6 89.6,-5.2 pad.1@90,-4.8
NetIC1_U16: IC1.U16 IC3.K14 pad.1@59.75,-4.25 pad.1@89.2,-5.6 | length 33.2
  Top Layer w0.13: IC1.U16@59.5,-4 pad.1@59.75,-4.25 ; IC3.K14@88.8,-5.2 pad.1@89.2,-5.6
  M1 w0.12: pad.1@59.75,-4.25 61.95,-4.25 64.2,-6.5 77.5,-6.5 79.3,-8.3 86.5,-8.3 pad.1@89.2,-5.6
NetIC1_U17: IC1.U17 IC3.J14 pad.1@61.875,-5.875 pad.1@90,-5.6 | length 35.7
  Top Layer w0.12: IC1.U17@60,-4 pad.1@61.875,-5.875
  Top Layer w0.13: IC3.J14@89.6,-5.2 pad.1@90,-5.6
  M1 w0.12: pad.1@61.875,-5.875 63.5,-7.5 76.4,-7.5 78.4,-9.5 88.2,-9.5 90,-7.7 pad.1@90,-5.6
NetIC2_19: IC2.19 IC4.H1 pad.1@70.6,0.5 | length 43.7
  Top Layer w0.12: IC2.19@29.33,-0.2 v1(30.7,-0.2)
  Top Layer w0.13: pad.1@70.6,0.5 IC4.H1@71,0.5
  M2 w0.12: v1(30.7,-0.2) 36.6,-0.2 49.7,-0.2 51.75,-2.25 60.25,-2.25 61.2,-1.3 68.8,-1.3 pad.1@70.6,0.5
NetIC2_21: IC2.21 IC4.G1 pad.1@70.6,1 | length 43.7
  Top Layer w0.12: IC2.21@29.33,0.2 30.2,0.2 32,2 v1(33,2)
  Top Layer w0.13: pad.1@70.6,1 IC4.G1@71,1
  M2 w0.12: v1(33,2) 36.25,2 37.5,0.75 51.25,0.75 52.25,1.75 69.85,1.75 pad.1@70.6,1
NetIC5_4: IC5.4 R126.1 R127.2 | length 2.2
  Top Layer w0.102: IC5.4@81.5,5.7 v1(81.5,6.3)
  Bottom Layer w0.102: R127.2@81.5,5.5 v1(81.5,6.3) 81.5,6.2 R126.1@81.5,6.9
NetIC5_5: IC5.5 R112.1 R113.2 | length 2.7
  Top Layer w0.102: IC5.5@81.5,3.9 81.5,3.3 81.6,3.2 R112.1@81.6,1.2
NetIC6_4: IC6.4 R115.1 R116.2 | length 2.3
  Top Layer w0.2: IC6.4@40.5,4.2 40.7,4 R115.1@41.4,4 R116.2@42.7,4
NetIC7_4: IC7.4 R123.1 R124.2 | length 2.3
  Top Layer w0.102: IC7.4@40.5,-5.5 41.5,-5.5 42.7,-5.5 R124.2@42.8,-5.4
NetP4_1: P4.1 P4.2 R230.2 | length 4.3
  Top Layer w0.203: P4.1@122.8,-5.6 P4.2@124,-5.6 R230.2@127.1,-5.6
NetP8_11: P8.11 P10.12 R210.1 | length 89.4
  Bottom Layer w0.102: R210.1@58.9,-10.3 60.5,-10.3 ; P8.11@65.8,-12 65.8,-9.25 65.5,-8.95 61.35,-8.95 60.5,-9.8 60.5,-10.3 ; P10.12@109.8,-12 109.8,-9.2 110.1,-8.9 116.65,-8.9 117,-9.25 117,-13.55 112.25,-18.3 76.5,-18.3 64.35,-18.3 60.5,-14.45 60.5,-10.3
NetP16_1: P16.1 P16.2 R231.2 | length 4.3
  Top Layer w0.203: P16.1@114.8,-5.6 P16.2@116,-5.6 R231.2@119.1,-5.6
NetP17_1: P17.1 P17.2 R232.2 | length 4.3
  Top Layer w0.203: P17.1@106.8,-5.6 P17.2@108,-5.6 R232.2@111.1,-5.6
NetQ1_2: Q1.2 R141.2 | length 1.1
  Top Layer w0.127: Q1.2@48.7,-5 48.8,-5.1 R141.2@49.75,-5.1
NetR222_2: R222.2 R240.1 | length 2
  Bottom Layer w0.203: R240.1@127.1,0.45 R222.2@127.1,2.45
NetR224_2: R224.2 R241.1 | length 2
  Bottom Layer w0.203: R241.1@119.1,0.45 R224.2@119.1,2.45
NetR226_2: R226.2 R242.1 | length 2.1
  Bottom Layer w0.203: R226.2@100.65,0 R242.1@102.7,0
ON0: IC3.A12 P2.1 pad.1@96.4,-4 R233.1 | length 177.2
  Top Layer w0.102: R233.1@7,18.5 v1(8.4,18.5) P2.1@14,18.5 ; IC3.A12@96,-3.6 pad.1@96.4,-4
  M1 w0.102: v1(8.4,18.5) 8.4,-10.3 15.1,-17 85.6,-17 85.9,-17.3 113.2,-17.3 117.5,-13 117.5,-9.2 116.4,-8.1 100.5,-8.1 pad.1@96.4,-4
ON1: IC3.A10 P3.1 pad.1@96.4,-2.4 R234.1 | length 120.7
  Top Layer w0.102: P3.1@31.1,-18.5 34.9,-18.5 35.4,-19 v1(37.4,-19) R234.1@38.4,-19 ; IC3.A10@96,-2 pad.1@96.4,-2.4
  M1 w0.102: v1(37.4,-19) 38.8,-17.6 84.8,-17.6 85.2,-18 113.6,-18 118.3,-13.3 118.3,-8.8 117,-7.5 101.5,-7.5 pad.1@96.4,-2.4
ON2: IC3.A6 P14.1 pad.1@96.4,1.6 R235.1 | length 85.6
  Top Layer w0.102: R235.1@91.9,18.1 97.9,18.1 P14.1@98.3,18.5 ; IC3.A6@96,1.2 pad.1@96.4,1.6
  M1 w0.102: v1(93.5,18.1) 95.4,16.2 117.85,16.2 123.8,10.25 123.8,-2.8 120.6,-6 104,-6 pad.1@96.4,1.6
ON3: IC3.A8 P15.1 pad.1@96.4,-0.8 R236.1 | length 47.3
  Top Layer w0.102: IC3.A8@96,-0.4 pad.1@96.4,-0.8 ; P15.1@116.1,-18.5 v1(123.3,-18.5) 124.1,-19.3 R236.1@124.1,-19.8
  M1 w0.102: pad.1@96.4,-0.8 102.5,-6.9 118,-6.9 123.3,-12.2 v1(123.3,-18.5)
PG0: IC3.A13 P2.2 pad.1@96.4,-4.8 R202.1 | length 178.3
  Top Layer w0.102: R202.1@7,20.1 v1(9,20.1) 13.15,24.25 P2.2@14,24.25 ; IC3.A13@96,-4.4 pad.1@96.4,-4.8
  M1 w0.102: v1(9,20.1) 9,-10 15.7,-16.7 85.8,-16.7 86.1,-17 112.9,-17 117.2,-12.7 117.2,-9.4 116.2,-8.4 100,-8.4 pad.1@96.4,-4.8
PG1: IC3.A11 P3.2 pad.1@96.4,-3.2 R204.1 | length 123.1
  Top Layer w0.102: P3.2@31.1,-24.25 32.85,-24.25 v1(36.7,-20.4) R204.1@38.4,-20.4 ; IC3.A11@96,-2.8 pad.1@96.4,-3.2
  M1 w0.102: v1(36.7,-20.4) 36.7,-18.7 38.1,-17.3 85,-17.3 85.4,-17.7 113.4,-17.7 117.9,-13.2 117.9,-9 116.7,-7.8 101,-7.8 pad.1@96.4,-3.2
PG2: IC3.A7 P14.2 pad.1@96.4,0.8 R206.1 | length 89.8
  Top Layer w0.102: R206.1@91.9,19.5 v1(92.9,19.5) 97.65,24.25 P14.2@98.3,24.25 ; IC3.A7@96,0.4 pad.1@96.4,0.8
  M1 w0.102: v1(92.9,19.5) 95.85,16.55 118.15,16.55 124.3,10.4 124.3,-3.1 121.1,-6.3 103.5,-6.3 pad.1@96.4,0.8
PG3: IC3.A9 P15.2 pad.1@96.4,-1.6 R208.1 | length 47
  Top Layer w0.102: IC3.A9@96,-1.2 pad.1@96.4,-1.6 ; P15.2@116.1,-24.25 116.15,-24.3 117.4,-24.3 v1(121.9,-19.8) R208.1@122.6,-19.8
  M1 w0.102: pad.1@96.4,-1.6 102,-7.2 117.8,-7.2 121.9,-11.3 v1(121.9,-19.8)
READY0: IC1.R2 R141.1 | length 3.1
  Top Layer w0.076: R141.1@49.75,-3.9 51.1,-3.9 51.75,-3.25 52.25,-3.25 IC1.R2@52.5,-3
REFCLKN: IC1.K17 IC4.P1 | length 12.5
  Top Layer w0.12: IC1.K17@60,-0.5 60.25,-0.25 62,-0.25 64.25,-2.5 68.3,-2.5 68.6,-2.2 69,-2.2 69.3,-2.5 69.6,-2.5 69.9,-2.2 70.3,-2.2 70.6,-2.5 IC4.P1@71,-2.5
REFCLKP: IC1.K16 IC4.R1 | length 12.5
  Top Layer w0.076: IC1.K16@59.5,-0.5 59.75,-0.75 60.25,-0.75
  Top Layer w0.12: 60.25,-0.75 61.75,-0.75 64,-3 IC4.R1@71,-3
RSSI: IC2.4 R147.2 R148.1 | length 32
  Top Layer w0.102: IC2.4@26.67,-3.4 27.35,-3.4 v1(29.1,-5.15)
  Bottom Layer w0.102: v1(29.1,-5.15) R148.1@30.45,-5.15 31.15,-5.15 32.7,-6.7 40,-6.7 40.9,-5.8 40.9,-3.2 44.7,0.6 49.25,0.6 50.3,1.65 R147.2@50.3,3.7
RSTB0: IC3.A1 P5.16 R239.1 | length 135.6
  Top Layer w0.102: v1(51.4,14.9) 61.75,14.9 62.45,15.6 113.25,15.6 113.75,15.1 113.75,14.15 111.1,11.5 101.9,11.5 96,5.6 IC3.A1@96,5.2
  M1 w0.102: v1(19.8,10.9) 19.8,12.45 24,16.65 27.35,16.65 29.1,14.9 v1(51.4,14.9)
  Bottom Layer w0.102: P5.16@19.8,12 v1(19.8,10.9) 19.8,9.2 20,9 26.5,9 28.2,10.7 R239.1@30.7,10.7
RSTB1: IC3.A2 P7.16 pad.1@68.9,6.9 R238.1 | length 41.1
  Top Layer w0.102: R238.1@68.9,5.4 pad.1@68.9,6.9 75.9,6.9 77.8,8.8 92.5,8.8 95.6,5.7 95.6,4.8 IC3.A2@96,4.4
  Bottom Layer w0.102: P7.16@63.4,12 63.4,9 65.5,6.9 pad.1@68.9,6.9
RSTB2: IC3.A3 P9.16 R237.1 | length 17.6
  Top Layer w0.102: IC3.A3@96,3.6 97.2,4.8 97.2,5.8 v1(99.9,8.5)
  Bottom Layer w0.102: R237.1@99.9,9.5 v1(99.9,8.5) 106.2,8.5 107,9.3 P9.16@107,12
SC_I2C: IC1.T3 P1.1 R143.2 | length 28.1
  Top Layer w0.076: 52.75,-4.25 52.75,-3.75 IC1.T3@53,-3.5
  Top Layer w0.102: v1(52.5,-9.7) 52.5,-4.5 52.75,-4.25 ; v1(55.8,-13.8) 57.5,-15.5 60.55,-15.5 ; 60.56,-15.51 60.55,-15.5 ; P1.1@68.2,-18.5 68.2,-15.9 67.8,-15.5 60.55,-15.5
  Top Layer w1: P1.1@68.18,-18.5 P1.1@68.2,-18.5
  Bottom Layer w0.102: v1(52.5,-9.7) R143.2@52.5,-10.4 53,-10.4 53.4,-10.8 53.4,-11.4 v1(55.8,-13.8)
T_EDIN00N: IC4.U5 P6.22 pad.1@73.25,-4.25 | length 54.1
  Top Layer w0.13: IC4.U5@73,-4 pad.1@73.25,-4.25
  Bottom Layer w0.12: P6.22@25.4,-13.85 25.4,-14.65 25.95,-15.2 39.2,-15.2 47.4,-7 68.5,-7
  Bottom Layer w0.13: 68.5,-7 71,-7 73.25,-4.75 pad.1@73.25,-4.25
T_EDIN00P: IC4.T5 P6.21 pad.1@72.75,-3.75 | length 54
  Top Layer w0.13: pad.1@72.75,-3.75 IC4.T5@73,-3.5
  Bottom Layer w0.12: P6.21@25.8,-13.85 25.8,-14.3 26.2,-14.7 27.4,-14.7 28,-14.1 29.2,-14.1 29.8,-14.7 31.2,-14.7 31.9,-14 32.9,-14 33.6,-14.7 38.9,-14.7 47.1,-6.5 70.85,-6.5 72.75,-4.6 pad.1@72.75,-3.75
T_EDIN02N: IC4.U7 P6.31 pad.1@74.25,-4.25 | length 60.2
  Top Layer w0.13: IC4.U7@74,-4 pad.1@74.25,-4.25
  Bottom Layer w0.12: P6.31@21.8,-13.85 21.8,-15.3 22.7,-16.2 41.7,-16.2 49.9,-8 71.5,-8 74.25,-5.25 pad.1@74.25,-4.25
T_EDIN02P: IC4.T7 P6.30 pad.1@73.75,-3.75 | length 60.1
  Top Layer w0.13: pad.1@73.75,-3.75 IC4.T7@74,-3.5
  Bottom Layer w0.12: P6.30@22.2,-13.85 22.2,-14.95 22.95,-15.7 41.4,-15.7 42.1,-15 42.1,-14 42.9,-13.2 43.9,-13.2 44.7,-12.4 44.7,-11.4 45.5,-10.6 46.5,-10.6 49.6,-7.5 71.2,-7.5 73.75,-4.95 pad.1@73.75,-3.75
T_EDIN10N: IC4.U11 P8.22 pad.1@76.25,-4.25 | length 18.4
  Top Layer w0.13: IC4.U11@76,-4 pad.1@76.25,-4.25
  Bottom Layer w0.12: P8.22@69,-13.85 69,-14.75 69.65,-15.4 73.7,-15.4 75.5,-13.6 75.5,-7.5 76.25,-6.75 pad.1@76.25,-4.25
T_EDIN10P: IC4.T11 P8.21 pad.1@75.75,-3.75 | length 18.4
  Top Layer w0.13: pad.1@75.75,-3.75 IC4.T11@76,-3.5
  Bottom Layer w0.12: P8.21@69.4,-13.85 69.4,-14.4 69.8,-14.8 70.5,-14.8 71,-14.3 71.7,-14.3 72.2,-14.8 73.3,-14.8 74.3,-13.8 74.3,-12.5 74.65,-12.15 74.65,-11.55 74.1,-11 74.1,-9.7 74.5,-9.3 74.5,-8.3 73.9,-7.7 73.9,-7 75.75,-5.15 pad.1@75.75,-3.75
T_EDIN12N: IC4.U13 P8.31 pad.1@77.25,-4.25 | length 25.6
  Top Layer w0.13: IC4.U13@77,-4 pad.1@77.25,-4.25
  Bottom Layer w0.12: P8.31@65.4,-13.85 65.4,-15.4 67.1,-17.1 74.4,-17.1 77.25,-14.25 pad.1@77.25,-4.25
T_EDIN12P: IC4.T13 P8.30 pad.1@76.75,-3.75 | length 25.7
  Top Layer w0.13: pad.1@76.75,-3.75 IC4.T13@77,-3.5
  Bottom Layer w0.12: P8.30@65.8,-13.85 65.8,-15.05 67.25,-16.5 71.2,-16.5 71.7,-16 72.6,-16 73.1,-16.5 74,-16.5 76.45,-14.05 76.45,-13.05 76.7,-12.8 76.7,-12.1 76.1,-11.5 76.1,-10.6 76.7,-10 76.7,-9.1 76.1,-8.5 76.1,-7.9 76.75,-7.25 pad.1@76.75,-3.75
T_EDIN20N: IC4.P17 P10.22 pad.1@78.75,-2.75 | length 49.8
  Top Layer w0.13: pad.1@78.75,-2.75 IC4.P17@79,-2.5
  Bottom Layer w0.12: pad.1@78.75,-2.75 78.75,-12 83.85,-17.1 84.4,-17.1 84.9,-16.6 85.6,-16.6 86.1,-17.1 88,-17.1 88.5,-16.6 89.5,-16.6 90,-17.1 91.1,-17.1 91.5,-16.7 92.7,-16.7 93.1,-17.1 94.3,-17.1 94.7,-16.7 95.9,-16.7 96.3,-17.1 97.4,-17.1 97.8,-16.7 98.9,-16.7 99.3,-17.1 100.4,-17.1 100.8,-16.7 101.9,-16.7 102.3,-17.1 110.65,-17.1 112.6,-15.15 P10.22@112.6,-13.85
T_EDIN20P: IC4.P16 P10.21 pad.1@78.25,-2.75 | length 49.9
  Top Layer w0.13: pad.1@78.25,-2.75 IC4.P16@78.5,-2.5
  Bottom Layer w0.12: pad.1@78.25,-2.75 78.25,-12.5 83.45,-17.7 111.3,-17.7 113,-16 P10.21@113,-13.85
T_EDIN22N: IC4.M17 P10.31 pad.1@79.25,-1.25 | length 44.1
  Top Layer w0.13: IC4.M17@79,-1.5 pad.1@79.25,-1.25
  Bottom Layer w0.12: pad.1@79.25,-1.25 79.75,-1.75 79.75,-11 84.25,-15.5 85.9,-15.5 86.4,-15 88.2,-15 88.7,-15.5 89.9,-15.5 90.4,-15 92.3,-15 92.8,-15.5 94.3,-15.5 94.9,-14.9 96.5,-14.9 97.1,-15.5 108.5,-15.5 109,-15 P10.31@109,-13.85
T_EDIN22P: IC4.M16 P10.30 pad.1@78.75,-1.75 | length 44.1
  Top Layer w0.13: IC4.M16@78.5,-1.5 pad.1@78.75,-1.75
  Bottom Layer w0.12: pad.1@78.75,-1.75 79.25,-2.25 79.25,-11.5 83.75,-16 108.75,-16 109.4,-15.35 P10.30@109.4,-13.85
T_EDIN30N: IC4.H17 P9.21 pad.1@79.25,0.25 | length 39.1
  Top Layer w0.13: IC4.H17@79,0.5 pad.1@79.25,0.25
  Bottom Layer w0.12: pad.1@79.35,0.25 80,0.9 80,9.2 81.8,11 83,11 83.8,11.8 85.3,11.8 86.1,11 87.4,11 88.2,11.8 89.6,11.8 90.4,11 98,11 101.6,14.6 105.15,14.6 105.4,14.35 P9.21@105.4,13.85
T_EDIN30P: IC4.H16 P9.22 pad.1@78.75,0.75 | length 39.2
  Top Layer w0.13: IC4.H16@78.5,0.5 pad.1@78.75,0.75
  Bottom Layer w0.12: pad.1@78.75,0.75 79.4,1.4 79.4,9.5 82.8,12.9 98.7,12.9 101,15.2 105.3,15.2 105.8,14.7 P9.22@105.8,13.85
T_EDIN32N: IC4.F17 P9.30 pad.1@78.75,1.75 | length 44.3
  Top Layer w0.13: pad.1@78.75,1.75 IC4.F17@79,1.5
  Bottom Layer w0.12: pad.1@78.75,1.75 78.75,9.75 83,14 84.2,14 85,14.8 86.8,14.8 87.6,14 89.1,14 89.9,14.8 91.6,14.8 92.4,14 93.9,14 94.7,14.8 96.4,14.8 97.2,14 98.7,14 100.4,15.7 108.05,15.7 109,14.75 P9.30@109,13.85
T_EDIN32P: IC4.F16 P9.31 pad.1@78.25,1.75 | length 44.3
  Top Layer w0.13: pad.1@78.25,1.75 IC4.F16@78.5,1.5
  Bottom Layer w0.12: pad.1@78.25,1.75 78.25,10.15 84.4,16.3 108.45,16.3 109.4,15.35 P9.31@109.4,13.85
T_EDIN40N: IC4.A14 P7.22 pad.1@77.25,4.25 | length 29.1
  Top Layer w0.13: pad.1@77.25,4.25 IC4.A14@77.5,4
  Bottom Layer w0.12: P7.22@62.2,13.85 62.2,14.95 63.75,16.5 73,16.5 74.8,14.7 74.8,14 74.3,13.5 73.6,13.5 73.1,13 73.1,12.4 73.6,11.9 74.2,11.9 74.8,11.3 74.8,9 77.25,6.55 pad.1@77.25,4.25
T_EDIN40P: IC4.B14 P7.21 pad.1@77.75,3.75 | length 29.1
  Top Layer w0.13: IC4.B14@77.5,3.5 pad.1@77.75,3.75
  Bottom Layer w0.12: P7.21@61.8,13.85 61.8,15.3 63.5,17 73.25,17 77,13.25 77,7.6 77.75,6.85 pad.1@77.75,3.75
T_EDIN42N: IC4.A12 P7.31 pad.1@76.25,4.25 | length 22.2
  Top Layer w0.13: pad.1@76.25,4.25 IC4.A12@76.5,4
  Bottom Layer w0.12: P7.31@65.8,13.85 65.8,14.8 66.5,15.5 70.2,15.5 71,14.7 71,9.4 70.6,9 70.6,7.9 71.3,7.2 75,7.2 76.25,5.95 pad.1@76.25,4.25
T_EDIN42P: IC4.B12 P7.30 pad.1@76.75,3.75 | length 22.2
  Top Layer w0.13: IC4.B12@76.5,3.5 pad.1@76.75,3.75
  Bottom Layer w0.12: P7.30@65.4,13.85 65.4,15.15 66.25,16 71,16 71.6,15.4 71.6,11.4 76.75,6.25 pad.1@76.75,3.75
T_EDIN50N: IC4.A10 P5.22 pad.1@75.25,4.25 | length 66.5
  Top Layer w0.13: pad.1@75.25,4.25 IC4.A10@75.5,4
  Bottom Layer w0.12: P5.22@18.6,13.85 18.6,14.8 20.3,16.5 28.4,16.5 29.9,15 31.5,15 32.4,15.9 33.7,15.9 34.6,15 36.1,15 37,15.9 38.3,15.9 39.2,15 41.1,15 42,15.9 43.3,15.9 44.2,15 47.9,15 55.9,7 63.6,7 64.6,6 74.4,6 75.25,5.15 pad.1@75.25,4.25
T_EDIN50P: IC4.B10 P5.21 pad.1@75.75,3.75 | length 66.5
  Top Layer w0.13: IC4.B10@75.5,3.5 pad.1@75.75,3.75
  Bottom Layer w0.12: P5.21@18.2,13.85 18.2,15.1 20.1,17 47.1,17 56.6,7.5 64,7.5 65,6.5 74.8,6.5 75.75,5.55 pad.1@75.75,3.75
T_EDIN52N: IC4.A8 P5.31 pad.1@74.25,4.25 | length 60.6
  Top Layer w0.13: pad.1@74.25,4.25 IC4.A8@74.5,4
  Bottom Layer w0.12: P5.31@22.2,13.85 22.2,14.8 22.9,15.5 26.5,15.5 30,12 31.2,12 31.8,12.6 33.4,12.6 34,12 35.3,12 35.9,12.6 37.2,12.6 37.8,12 39.3,12 40,12.7 41.1,12.7 41.8,12 43.2,12 43.9,12.7 45,12.7 45.7,12 48.7,12 54.7,6 62.7,6 63.7,5 73.8,5 74.25,4.55 pad.1@74.25,4.25
T_EDIN52P: IC4.B8 P5.30 pad.1@74.75,3.75 | length 60.6
  Top Layer w0.13: IC4.B8@74.5,3.5 pad.1@74.75,3.75
  Bottom Layer w0.12: P5.30@21.8,13.85 21.8,15.2 22.6,16 27.3,16 29.3,14 47.8,14 55.3,6.5 63.2,6.5 64.2,5.5 74,5.5 74.75,4.75 pad.1@74.75,3.75
Vref: IC1.D2 R144.2 R145.2 R201.2 R243.2 | length 12.2
  Top Layer w0.076: 51.75,2.75 52.25,2.75 IC1.D2@52.5,2.5
  Top Layer w0.102: R243.2@41.65,1.7 R144.2@42.5,1.7 42.95,1.7 43.15,1.5 45.15,1.5 45.35,1.7 R201.2@45.35,2.1 46.15,2.1 46.55,2.5 49.2,2.5 ; R145.2@49.2,2.1 49.2,2.5 ; 51.75,2.75 51.5,2.5 49.2,2.5
pads on no net: IC1.A3 IC1.A4 IC1.A5 IC1.A6 IC1.A7 IC1.A9 IC1.A11 IC1.A13 IC1.B3 IC1.B4 IC1.B5 IC1.B6 IC1.B7 IC1.B9 IC1.B11 IC1.B13 IC1.C2 IC1.C6 IC1.C7 IC1.C8 IC1.C10 IC1.C12 IC1.C16 IC1.C17 IC1.D6 IC1.D7 IC1.D8 IC1.D10 IC1.D12 IC1.D14 IC1.D15 IC1.D16 IC1.D17 IC1.E2 IC1.E7 IC1.E10 IC1.E11 IC1.E12 IC1.E13 IC1.E14 IC1.E15 IC1.E16 IC1.E17 IC1.F7 IC1.F10 IC1.F11 IC1.F12 IC1.F13 IC1.F14 IC1.F15 IC1.G14 IC1.G15 IC1.G16 IC1.G17 IC1.H4 IC1.H14 IC1.H15 IC1.J4 IC1.J14 IC1.J15 IC1.J16 IC1.J17 IC1.K4 IC1.K14 IC1.K15 IC1.L4 IC1.L5 IC1.L7 IC1.L8 IC1.L9 IC1.L14 IC1.L15 IC1.L16 IC1.L17 IC1.M4 IC1.M5 IC1.M6 IC1.M7 IC1.M9 IC1.M10 IC1.M11 IC1.M14 IC1.M15 IC1.N4 IC1.N5 IC1.N6 IC1.N7 IC1.N8 IC1.N9 IC1.N10 IC1.N11 IC1.N12 IC1.N14 IC1.N15 IC1.N16 IC1.N17 IC1.P1 IC1.P6 IC1.P8 IC1.P10 IC1.P11 IC1.P12 IC1.P15 IC1.R1 IC1.R3 IC1.R6 IC1.R8 IC1.R10 IC1.R11 IC1.R12 IC1.R15 IC1.T1 IC1.T2 IC1.T6 IC1.T8 IC1.T12 IC1.T14 IC1.T15 IC1.U1 IC1.U6 IC1.U8 IC1.U12 IC1.U14 IC1.U15 IC2.2 IC2.20 IC2.22 IC2.25 IC2.26 IC2.27 IC2.28 IC2.31 IC2.33 IC3.A4 IC3.A5 IC3.A14 IC3.B1 IC3.B2 IC3.B3 IC3.B4 IC3.B5 IC3.B6 IC3.B7 IC3.B8 IC3.B9 IC3.B10 IC3.B11 IC3.B12 IC3.B13 IC3.B14 IC3.C1 IC3.C2 IC3.C3 IC3.C4 IC3.C5 IC3.C6 IC3.C7 IC3.C8 IC3.C9 IC3.C10 IC3.C11 IC3.C12 IC3.C13 IC3.C14 IC3.D1 IC3.D2 IC3.D3 IC3.D12 IC3.D13 IC3.D14 IC3.E1 IC3.E2 IC3.E3 IC3.E12 IC3.E13 IC3.E14 IC3.F1 IC3.F2 IC3.F3 IC3.F12 IC3.F13 IC3.F14 IC3.G1 IC3.G2 IC3.G3 IC3.G4 IC3.H1 IC3.H2 IC3.H3 IC3.H4 IC3.J1 IC3.J2 IC3.J3 IC3.J4 IC3.K1 IC3.K2 IC3.K3 IC3.L1 IC3.L2 IC3.L3 IC3.M1 IC3.M2 IC3.M3 IC3.M7 IC3.M8 IC3.M9 IC3.M10 IC3.M11 IC3.M12 IC3.N1 IC3.N2 IC3.N3 IC3.N5 IC3.N7 IC3.N8 IC3.N9 IC3.N10 IC3.N11 IC3.N12 IC3.N13 IC3.N14 IC3.P1 IC3.P2 IC3.P3 IC3.P5 IC4.A1 IC4.A2 IC4.A3 IC4.A4 IC4.A5 IC4.A6 IC4.A7 IC4.A9 IC4.A11 IC4.A13 IC4.A15 IC4.A16 IC4.A17 IC4.B1 IC4.B2 IC4.B3 IC4.B4 IC4.B5 IC4.B6 IC4.B7 IC4.B9 IC4.B11 IC4.B13 IC4.B15 IC4.B16 IC4.B17 IC4.C1 IC4.C2 IC4.C3 IC4.C4 IC4.C5 IC4.C6 IC4.C7 IC4.C8 IC4.C9 IC4.C10 IC4.C11 IC4.C12 IC4.C13 IC4.C14 IC4.C15 IC4.C16 IC4.C17 IC4.D1 IC4.D2 IC4.D4 IC4.D5 IC4.D6 IC4.D7 IC4.D8 IC4.D9 IC4.D10 IC4.D11 IC4.D12 IC4.D13 IC4.D14 IC4.D15 IC4.D16 IC4.D17 IC4.E1 IC4.E2 IC4.E5 IC4.E6 IC4.E7 IC4.E10 IC4.E11 IC4.E12 IC4.E13 IC4.E14 IC4.E15 IC4.E16 IC4.E17 IC4.F5 IC4.F6 IC4.F7 IC4.F10 IC4.F11 IC4.F12 IC4.F13 IC4.F14 IC4.F15 IC4.G14 IC4.G15 IC4.G16 IC4.G17 IC4.H4 IC4.H14 IC4.H15 IC4.J4 IC4.J14 IC4.J15 IC4.J16 IC4.J17 IC4.K4 IC4.K14 IC4.K15 IC4.K16 IC4.K17 IC4.L1 IC4.L4 IC4.L5 IC4.L6 IC4.L7 IC4.L8 IC4.L9 IC4.L14 IC4.L15 IC4.L16 IC4.L17 IC4.M1 IC4.M4 IC4.M5 IC4.M6 IC4.M7 IC4.M8 IC4.M9 IC4.M10 IC4.M11 IC4.M14 IC4.M15 IC4.N4 IC4.N5 IC4.N6 IC4.N7 IC4.N8 IC4.N9 IC4.N10 IC4.N11 IC4.N12 IC4.N13 IC4.N14 IC4.N15 IC4.N16 IC4.N17 IC4.P4 IC4.P5 IC4.P6 IC4.P7 IC4.P8 IC4.P9 IC4.P10 IC4.P11 IC4.P12 IC4.P13 IC4.P14 IC4.P15 IC4.R2 IC4.R3 IC4.R4 IC4.R5 IC4.R6 IC4.R7 IC4.R8 IC4.R9 IC4.R10 IC4.R11 IC4.R12 IC4.R13 IC4.R14 IC4.R15 IC4.R16 IC4.R17 IC4.T1 IC4.T2 IC4.T4 IC4.T6 IC4.T8 IC4.T9 IC4.T10 IC4.T12 IC4.T14 IC4.T15 IC4.T16 IC4.T17 IC4.U1 IC4.U4 IC4.U6 IC4.U8 IC4.U9 IC4.U10 IC4.U12 IC4.U14 IC4.U15 IC4.U16 IC4.U17 IC5.2 IC5.3 IC6.2 IC6.5 IC6.7 IC7.2 IC7.5 IC7.7 JMP1.9 JMP2.9 P1.3 P1.5 P1.7 P1.10 P2.3 P2.4 P3.3 P3.4 P4.4 P6.16 P8.16 P10.16 P11.1 P11.2 P12.5 P14.3 P14.4 P15.3 P15.4 P16.4 P17.4
copper on no net: | length 51
  Top Layer w0.152: 126.75,-20 126.75,-21.75 129.25,-21.75 129.25,-20 ; 126.75,-20 126.75,-18.25 ; 126.75,-20 129.25,-20 ; 126.75,-18.25 126.75,-16.25 ; 126.75,-18.25 129.25,-18.25 ; 126.75,-16.25 126.75,-14.5 ; 126.75,-16.25 129.25,-16.25 ; 126.75,-14.5 126.75,-12.75 ; 126.75,-14.5 129.25,-14.5 ; 126.75,-12.75 126.75,-11 ; 126.75,-12.75 129.25,-12.75 ; 126.75,-11 126.75,-9.25 ; 126.75,-11 129.25,-11 ; 126.75,-9.25 126.75,-7.5 129.25,-7.5 129.25,-9.25 ; 126.75,-9.25 129.25,-9.25 ; 129.25,-20 129.25,-18.25 ; 129.25,-18.25 129.25,-16.25 ; 129.25,-16.25 129.25,-14.5 ; 129.25,-14.5 129.25,-12.75 ; 129.25,-12.75 129.25,-11 ; 129.25,-11 129.25,-9.25

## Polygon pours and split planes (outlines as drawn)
GND on plane 1 (split plane): 271 vertices, not listed, extent 0.51,-27.74 129.79,27.74
GND on plane 4 (split plane): 271 vertices, not listed, extent 0.51,-27.74 129.79,27.74
GND on plane 2 (split plane): 113.921,15.846 113.921,9.304 112.796,8.179 102.554,8.179 98.942,11.792 98.9,11.82 98.85,11.829 82.05,11.829 82,11.82 81.958,11.792 76.646,6.479 64.1,6.479 64.05,6.47 64.008,6.442 59.946,2.379 55.554,2.379 55.092,2.842 55.05,2.87 55,2.879 54.304,2.879 45.292,11.892 45.25,11.92 45.2,11.929 31.3,11.929 31.25,11.92 31.208,11.892 27.496,8.179 18.879,8.179 18.879,11.346 22.192,14.658 22.22,14.7 22.229,14.75 22.229,15.646 23.754,17.171 112.596,17.171
GND on plane 2 (split plane): 77.608,-3.292 77.65,-3.32 77.7,-3.329 85.2,-3.329 85.25,-3.32 85.292,-3.292 85.654,-2.929 91.996,-2.929 97.858,-8.792 97.9,-8.82 97.95,-8.829 111.996,-8.829 113.121,-9.954 113.121,-15.821 94.95,-15.821 94.929,-15.825 94.908,-15.821 78.4,-15.821 78.35,-15.83 78.308,-15.858 77.746,-16.421 65.504,-16.421 64.992,-15.908 64.95,-15.88 64.9,-15.871 18.304,-15.871 17.379,-14.946 17.379,-9.804 18.054,-9.129 42,-9.129 42.05,-9.12 42.092,-9.092 47.804,-3.379 51.25,-3.379 51.3,-3.37 51.342,-3.342 52.304,-2.379 73.75,-2.379 73.8,-2.37 73.842,-2.342 74.304,-1.879 76.196,-1.879
1V2_RB on plane 2 (split plane): 271 vertices, not listed, extent 0.51,-27.74 129.79,27.74
1V2C on plane 3 (split plane): 118.871,19 118.88,18.95 118.908,18.908 118.95,18.88 119,18.871 127.471,18.871 127.471,7.129 111.329,7.129 111.329,11.471 112.5,11.471 112.55,11.48 112.592,11.508 114.092,13.008 114.12,13.05 114.129,13.1 114.129,16.1 114.12,16.15 114.092,16.192 114.05,16.22 114,16.229 81.5,16.229 81.45,16.22 81.408,16.192 74.046,8.829 65.729,8.829 65.729,11.746 66.354,12.371 70.6,12.371 70.65,12.38 70.692,12.408 70.72,12.45 70.729,12.5 70.729,17.471 75.7,17.471 75.75,17.48 75.792,17.508 78.754,20.471 94.6,20.471 94.65,20.48 94.692,20.508 100.554,26.371 118.871,26.371
1V5D on plane 3 (split plane): 91.871,-4.271 89.729,-4.271 89.729,2.8 89.72,2.85 89.692,2.892 89.65,2.92 89.6,2.929 83.854,2.929 82.629,4.154 82.629,5.471 91.871,5.471
1V2D on plane 3 (split plane): 111.071,7 111.08,6.95 111.108,6.908 111.15,6.88 111.2,6.871 129.79,6.871 129.79,-22.74 127.3,-22.74 127.299,-22.74 127.081,-22.749 126.864,-22.778 126.65,-22.825 126.441,-22.891 126.239,-22.975 126.045,-23.076 125.86,-23.194 125.686,-23.327 125.525,-23.475 125.377,-23.636 125.244,-23.81 125.126,-23.995 125.025,-24.189 124.941,-24.391 124.875,-24.6 124.828,-24.814 124.799,-25.031 124.79,-25.249 124.79,-25.25 124.79,-27.74 97.629,-27.74 97.629,-17.829 113.25,-17.829 113.3,-17.82 113.342,-17.792 113.37,-17.75 113.379,-17.7 113.379,-8.9 113.37,-8.85 113.342,-8.808 113.3,-8.78 113.25,-8.771 109.8,-8.771 109.75,-8.78 109.708,-8.808 109.68,-8.85 109.671,-8.9 109.671,-11.371 101.829,-11.371 101.829,8.771 105.1,8.771 105.15,8.78 105.192,8.808 105.22,8.85 105.229,8.9 105.229,11.471 111.071,11.471
1V5A on plane 3 (split plane): 95.371,-8.371 85.654,-8.371 80.029,-2.746 80.029,6.846 83.054,9.871 95.371,9.871
LV_RB on plane 3 (split plane): 174 vertices, not listed, extent 0.51,4.929 129.79,27.74
1V2A on plane 3 (split plane): 34.271,17.729 14.5,17.729 14.45,17.72 14.408,17.692 14.38,17.65 14.371,17.6 14.371,9 14.38,8.95 14.408,8.908 14.45,8.88 14.5,8.871 18.8,8.871 18.85,8.88 18.892,8.908 18.92,8.95 18.929,9 18.929,11.871 28.871,11.871 28.871,6.129 25,6.129 24.95,6.12 24.908,6.092 24.88,6.05 24.871,6 24.871,-11.371 20.129,-11.371 20.129,-8 20.12,-7.95 20.092,-7.908 20.05,-7.88 20,-7.871 0.51,-7.871 0.51,4.671 3.4,4.671 3.45,4.68 3.492,4.708 3.52,4.75 3.529,4.8 3.529,20.571 6.6,20.571 6.65,20.58 6.692,20.608 12.154,26.071 34.271,26.071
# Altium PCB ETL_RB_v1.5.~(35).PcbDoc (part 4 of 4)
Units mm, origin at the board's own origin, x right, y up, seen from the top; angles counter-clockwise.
Board outline 130.3 x 56.5 mm, 8 copper layers (Top Layer, plane 1, M1, plane 2, plane 3, M2, plane 4, Bottom Layer), stack 0.937 mm thick; 212 components, 186 nets, 1961 pads, 953 vias.
Unrouted connection lines stored in the file: 395.

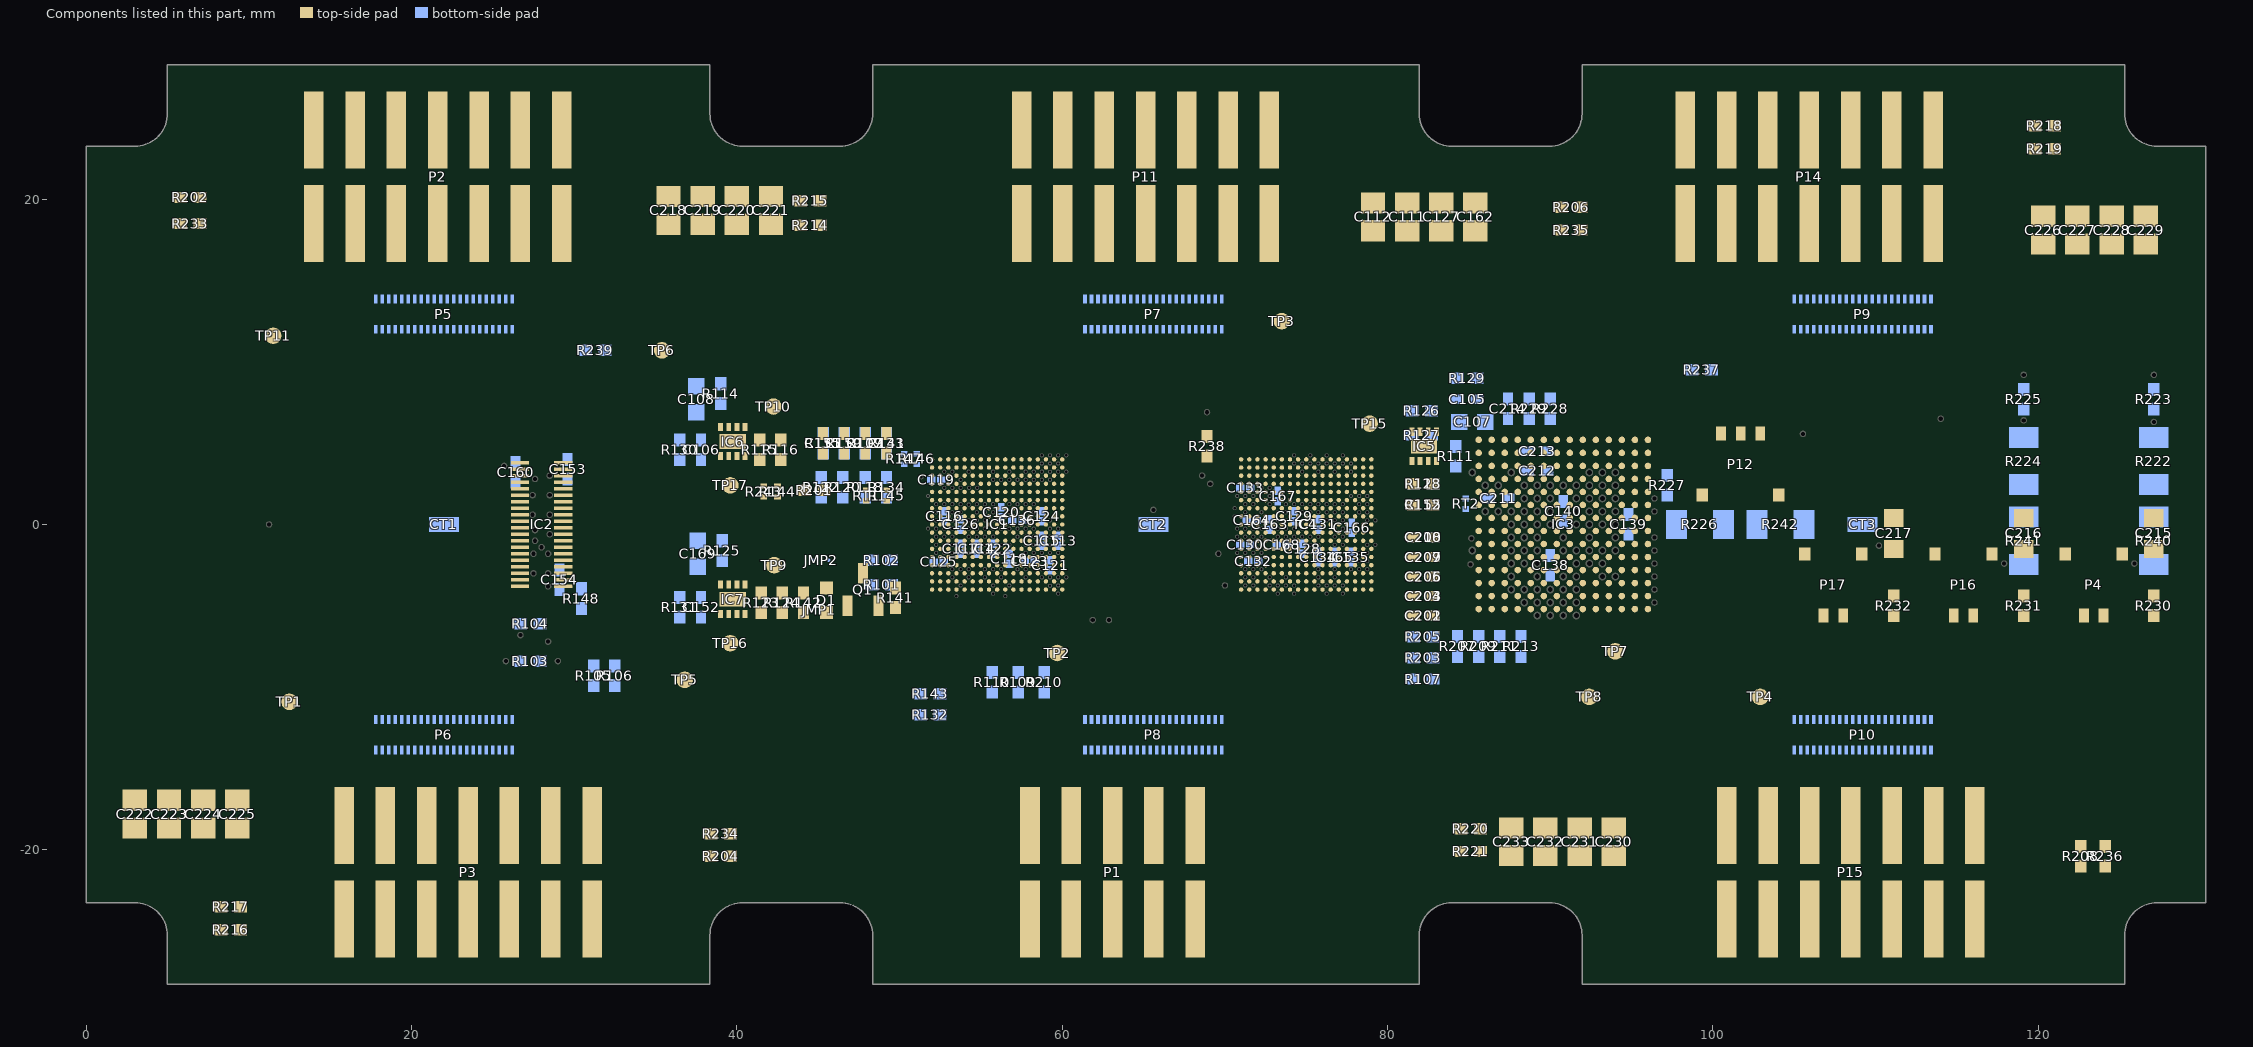
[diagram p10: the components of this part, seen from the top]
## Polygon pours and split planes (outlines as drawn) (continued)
GND on plane 3 (split plane): 70.471,12.629 66.3,12.629 66.25,12.62 66.208,12.592 65.508,11.892 65.48,11.85 65.471,11.8 65.471,8.7 65.48,8.65 65.508,8.608 65.55,8.58 65.6,8.571 74.1,8.571 74.15,8.58 74.192,8.608 81.554,15.971 113.871,15.971 113.871,13.154 112.446,11.729 105.1,11.729 105.05,11.72 105.008,11.692 104.98,11.65 104.971,11.6 104.971,9.029 101.7,9.029 101.65,9.02 101.608,8.992 101.58,8.95 101.571,8.9 101.571,-11.5 101.58,-11.55 101.608,-11.592 101.65,-11.62 101.7,-11.629 109.8,-11.629 109.85,-11.62 109.892,-11.592 109.92,-11.55 109.929,-11.5 109.929,-9.029 113.121,-9.029 113.121,-17.571 97.5,-17.571 97.45,-17.58 97.408,-17.608 97.38,-17.65 97.371,-17.7 97.371,-27.74 92.46,-27.74 92.46,-25.25 92.46,-25.249 92.451,-25.031 92.422,-24.814 92.375,-24.6 92.309,-24.391 92.225,-24.189 92.124,-23.995 92.006,-23.81 91.873,-23.636 91.725,-23.475 91.564,-23.327 91.39,-23.194 91.205,-23.076 91.011,-22.975 90.809,-22.891 90.6,-22.825 90.386,-22.778 90.169,-22.749 89.951,-22.74 89.95,-22.74 83.95,-22.74 83.949,-22.74 83.731,-22.749 83.514,-22.778 83.3,-22.825 83.091,-22.891 82.889,-22.975 82.695,-23.076 82.51,-23.194 82.336,-23.327 82.175,-23.475 82.027,-23.636 81.894,-23.81 81.776,-23.995 81.675,-24.189 81.591,-24.391 81.525,-24.6 81.478,-24.814 81.449,-25.031 81.44,-25.249 81.44,-25.25 81.44,-27.74 75.129,-27.74 75.129,-8.5 75.12,-8.45 75.092,-8.408 75.05,-8.38 75,-8.371 60.5,-8.371 60.45,-8.38 60.408,-8.408 60.38,-8.45 60.371,-8.5 60.371,-10.5 60.38,-10.55 60.408,-10.592 62.008,-12.192 62.05,-12.22 62.1,-12.229 69.771,-12.229 69.771,-16.371 17.629,-16.371 17.629,-14.054 20.054,-11.629 25,-11.629 25.05,-11.62 25.092,-11.592 25.12,-11.55 25.129,-11.5 25.129,5.871 29,5.871 29.05,5.88 29.092,5.908 29.12,5.95 29.129,6 29.129,12 29.12,12.05 29.092,12.092 29.05,12.12 29,12.129 18.8,12.129 18.75,12.12 18.708,12.092 18.68,12.05 18.671,12 18.671,9.129 14.629,9.129 14.629,17.471 70.471,17.471
1V2B on plane 3 (split plane): 19.871,-11.446 17.408,-13.908 17.38,-13.95 17.371,-14 17.371,-16.5 17.38,-16.55 17.408,-16.592 17.45,-16.62 17.5,-16.629 69.9,-16.629 69.95,-16.62 69.992,-16.592 70.02,-16.55 70.029,-16.5 70.029,-12.1 70.02,-12.05 69.992,-12.008 69.95,-11.98 69.9,-11.971 62.154,-11.971 60.629,-10.446 60.629,-8.629 74.871,-8.629 74.871,-27.74 48.86,-27.74 48.86,-25.25 48.86,-25.249 48.851,-25.031 48.822,-24.814 48.775,-24.6 48.709,-24.391 48.625,-24.189 48.524,-23.995 48.406,-23.81 48.273,-23.636 48.125,-23.475 47.964,-23.327 47.79,-23.194 47.605,-23.076 47.411,-22.975 47.209,-22.891 47,-22.825 46.786,-22.778 46.569,-22.749 46.351,-22.74 46.35,-22.74 40.35,-22.74 40.349,-22.74 40.131,-22.749 39.914,-22.778 39.7,-22.825 39.491,-22.891 39.289,-22.975 39.095,-23.076 38.91,-23.194 38.736,-23.327 38.575,-23.475 38.427,-23.636 38.294,-23.81 38.176,-23.995 38.075,-24.189 37.991,-24.391 37.925,-24.6 37.878,-24.814 37.849,-25.031 37.84,-25.249 37.84,-25.25 37.84,-27.74 5.51,-27.74 5.51,-25.25 5.51,-25.249 5.501,-25.031 5.472,-24.814 5.425,-24.6 5.359,-24.391 5.275,-24.189 5.174,-23.995 5.056,-23.81 4.923,-23.636 4.775,-23.475 4.614,-23.327 4.44,-23.194 4.255,-23.076 4.061,-22.975 3.859,-22.891 3.65,-22.825 3.436,-22.778 3.219,-22.749 3.001,-22.74 3,-22.74 0.51,-22.74 0.51,-8.129 19.871,-8.129

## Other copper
Top Layer:
  rectangle net GND: 38.25,4.6 38.75,5.75
  rectangle net GND: 38.25,4.65 39.05,5.55
  rectangle net GND: 119.5,18.3 127.4,21
  rectangle net 1V2C: 119.5,15.2 127.4,17.9
  rectangle net LV_RB: 59.5,20.7 60.6,22.1
  rectangle net LV_RB: 58.6,23.3 59.6,26.6
  rectangle net GND: 78.3,19.1 86.1,21.5
  rectangle net 1V2_RB: 75.4,16.2 86.1,18.7
  rectangle net GND: 34.8,19.5 42.8,21.6
  rectangle net 1V2A: 31.6,16.1 42.9,19.1
  rectangle net GND: 2.3,-21.1 10.1,-18
  rectangle net 1V2B: 2.3,-17.6 10,-14.6
  rectangle net GND: 21.4,-20.8 27.6,-16.1
  rectangle net GND: 22.9,-26.7 27.6,-20.7
  rectangle net 1V2B: 13,-26.6 21,-21.9
  rectangle net 1V2B: 13,-22.2 19,-16.1
  rectangle net GND: 86.9,-21.8 97.1,-19.8
  rectangle net 1V2D: 86.9,-19.2 98.6,-16.2
  region net 1V2_RB: 75.6,22.2 69.6,22.2 69.6,16.1 75.6,16.1
  region net 1V2_RB: 75.6,26.6 68,26.6 68,21.9 75.6,21.9
  region net GND: 65.7,26.6 61,26.6 61,20.6 65.7,20.6
  region net GND: 67.5,20.9 61,20.9 61,16.1 67.5,16.1
  region net 1V2A: 32.1,22.3 26.1,22.3 26.1,16.1 32.1,16.1
  region net 1V2A: 32.1,26.6 24.5,26.6 24.5,21.9 32.1,21.9
  region net GND: 22.3,26.7 17.5,26.7 17.5,20.7 22.3,20.7
  region net GND: 24,20.9 17.5,20.9 17.5,16.1 24,16.1
  region net 1V2C: 116.1,22.2 110.4,22.2 110.4,16.1 116.1,16.1
  region net 1V2C: 116.1,26.6 108.7,26.6 108.7,21.9 116.1,21.9
  region net GND: 106.5,26.6 101.8,26.6 101.8,20.6 106.5,20.6
  region net GND: 108.3,20.9 101.8,20.9 101.8,16.1 108.3,16.1
  rectangle net 1V2D: 98,-22.2 104,-16.1
  rectangle net 1V2D: 98,-26.6 106,-21.9
  rectangle net GND: 107.9,-26.6 112.6,-20.6
  rectangle net GND: 106.4,-20.9 112.6,-16.2
  rectangle net GND: 97.6,1.4 99.7,3.3
  rectangle net BV2: 108.8,-2.8 111.7,-0.9
  rectangle: 113.3,-2.8 114.4,-0.9
  rectangle: 121.3,-2.9 122.5,-0.9
  rectangle net BV1: 116.8,-2.9 119.7,-0.9
  rectangle net BV0: 124.8,-2.9 127.7,-0.9
  rectangle: 103.7,-2.8 106,-0.9
  rectangle: 103.7,1.4 105.8,3.3
  rectangle net GND: 38,-5.15 38.7,-3.9
  rectangle net GND: 38.6,-5.1 39.05,-4.15
  rectangle net GND: 80.2,4.35 81.6,5.25
  text "1" at 128.746,-21.121 h1.52 r90
  text "'.Pcb_File_Name_No_Path'     '.Layer_Name'    '.Print_Date'    '.Print_Time'" at 9.954,-31.338 h1.52
M1:
  text "3" at 128.746,-17.746 h1.52 r90
  text "'.Pcb_File_Name_No_Path'    '.Layer_Name'    '.Print_Date'    '.Print_Time'" at 9.954,-31.392 h1.52
M2:
  text "6" at 128.746,-12.371 h1.52 r90
  text "'.Pcb_File_Name_No_Path'    '.Layer_Name'    '.Print_Date'    '.Print_Time'" at 9.954,-31.392 h1.52
Bottom Layer:
  rectangle net GND: 38.05,4.6 38.75,5.75
  rectangle net GND: 37.5,-5.1 38.7,-3.9
  rectangle net GND: 58.7,12.425 70.1,13.425
  rectangle net GND: 26.1,2.1 27.9,3.1
  rectangle net GND: 28.2,2.4 29.9,3.3
  rectangle net GND: 28.1,-3.3 29.4,-2.4
  rectangle net GND: 14.8,9.3 17.9,12.7
  rectangle net GND: 58.7,9.3 61.4,12.6
  rectangle net GND: 63.7,9.3 65.5,12.6
  rectangle net GND: 107.3,9.3 109.1,12.6
  rectangle net GND: 101.7,9.3 105.1,13.425
  rectangle net GND: 101.7,12.425 113.7,13.425
  rectangle net GND: 20.1,9.3 21.9,12.6
  rectangle net GND: 22.1,-12.6 23.9,-11.4
  rectangle net GND: 22.1,-11.5 24.7,-9.3
  rectangle net GND: 110.1,-12.6 111.1,-11.4
  rectangle net GND: 110.1,-11.5 111.9,-9.3
  rectangle net GND: 113.3,-12.7 116.7,-9.3
  rectangle net GND: 67.4,-11.5 68.3,-9.3
  rectangle net GND: 66.1,-12.6 67.5,-9.3
  rectangle net GND: 69.7,-12.7 73.1,-9.3
  rectangle net GND: 26.1,-12.7 29.5,-9.3
  region net GND: 29.5,-12.425 17.5,-12.425 17.5,-13.425 29.5,-13.425
  region net GND: 73.1,-12.425 61.1,-12.425 61.1,-13.425 73.1,-13.425
  region net GND: 116.7,-12.425 104.7,-12.425 104.7,-13.425 116.7,-13.425
  rectangle net GND: 14.8,12.4 26.3,13.4
  rectangle net 1V2_RB: 25.3,3.4 26.3,4.2
  rectangle net 2V5TX: 29.85,3.6 30.65,4.4
  rectangle net 2V5RX: 28.1,-4.4 28.9,-3.6
  rectangle net 1V2C: 67.7,9.275 69.5,12.275
  rectangle net 1V2C: 65.7,9.275 67.5,12.275
  rectangle net 1V2D: 109.3,9.275 111.1,12.275
  rectangle net 1V2C: 111.3,9.275 113.1,12.275
  region net 1V2D: 109.1,-9.275 107.3,-9.275 107.3,-12.275 109.1,-12.275
  region net 1V2D: 107.1,-9.275 105.3,-9.275 105.3,-12.275 107.1,-12.275
  region net 1V2B: 65.5,-9.275 63.7,-9.275 63.7,-12.275 65.5,-12.275
  region net 1V2B: 63.5,-9.275 61.7,-9.275 61.7,-12.275 63.5,-12.275
  region net 1V2B: 19.9,-9.275 18.1,-9.275 18.1,-12.275 19.9,-12.275
  region net 1V2A: 21.9,-9.275 20.1,-9.275 20.1,-12.275 21.9,-12.275
  rectangle net 1V2A: 22.1,9.275 23.9,12.275
  rectangle net 1V2A: 24.1,9.275 25.9,12.275
  text "8" at 128.746,-8.871 h1.52 r90
  text "'.Pcb_File_Name_No_Path'    '.Layer_Name'    '.Print_Date'    '.Print_Time'" at 9.954,-31.338 h1.52
plane 1 (plane layer: these items are gaps in the copper):
  rectangle: 12,-5 24.2,5
  rectangle: 126.75,-18.25 129.25,-7.5
  text "2" at 128.746,-19.621 h1.52 r90
  text "'.Pcb_File_Name_No_Path'    '.Layer_Name'    '.Print_Date'    '.Print_Time'" at 9.954,-31.338 h1.52
plane 2 (plane layer: these items are gaps in the copper):
  rectangle: 12,-5 24.2,5
  rectangle: 126.75,-20 129.25,-16.25
  rectangle: 126.75,-14.5 129.25,-7.5
  lines w0.254: 94.908,-15.95 78.4,-15.95 77.8,-16.55 71,-16.55 65.45,-16.55 64.9,-16 18.25,-16 17.25,-15 17.25,-9.75 18,-9 42,-9 47.75,-3.25 51.25,-3.25 52.25,-2.25 63.25,-2.25 73.75,-2.25 74.25,-1.75 76.25,-1.75 77.7,-3.2 82,-3.2 85.2,-3.2 85.6,-2.8 92.05,-2.8 97.95,-8.7 112.05,-8.7 113.25,-9.9 113.25,-15.95 94.95,-15.95 ; 18.75,8.05 18.75,11.4 22.1,14.75 22.1,15.7 23.7,17.3 112.65,17.3 114.05,15.9 114.05,9.25 112.85,8.05 102.5,8.05 98.85,11.7 82.05,11.7 76.7,6.35 64.1,6.35 60,2.25 55.5,2.25 55,2.75 54.25,2.75 45.2,11.8 31.3,11.8 27.55,8.05 18.75,8.05
  text "4" at 128.746,-15.871 h1.52 r90
  text "'.Pcb_File_Name_No_Path'    '.Layer_Name'    '.Print_Date'    '.Print_Time'" at 9.954,-31.338 h1.52
plane 3 (plane layer: these items are gaps in the copper):
  rectangle: 126.75,-20 129.25,-14.5
  rectangle: 126.75,-12.75 129.25,-7.5
  lines w0.254: 0,-8 20,-8 20,-11.5 ; 0,4.8 3.4,4.8 3.4,20.7 6.6,20.7 12.1,26.2 34.4,26.2 34.4,17.6 ; 28.5,28.2 28.5,28.3 ; 29,28.2 29,28.3 ; 70.6,17.6 70.6,12.5 69.2,12.5 66.3,12.5 65.6,11.8 65.6,8.7 74.1,8.7 81.5,16.1 114,16.1 114,13.1 112.5,11.6 111.2,11.6 ; 75,-28 75,-8.5 60.5,-8.5 60.5,-10.5 62.1,-12.1 69.9,-12.1 69.9,-16.5 17.5,-16.5 17.5,-14 20,-11.5 ; 97.5,-28.3 97.5,-17.7 113.25,-17.7 113.25,-8.9 109.8,-8.9 109.8,-11.5 101.7,-11.5 101.7,8.9 105.1,8.9 105.1,11.6 111.2,11.6 ; 127.6,7 127.6,19 119,19 119,26.5 100.5,26.5 94.6,20.6 78.7,20.6 75.7,17.6 ; 130.3,7 130.3,7.1 130.2,7 111.2,7 111.2,11.6 ; 20,-11.5 25,-11.5 25,6 29,6 29,12 18.8,12 18.8,9 14.5,9 14.5,17.6 75.7,17.6 ; 75.7,17.6 75.7,17.6 ; 79.9,-2.8 85.6,-8.5 95.5,-8.5 95.5,10 83,10 79.9,6.9 79.9,-2.8 ; 82.5,4.1 83.8,2.8 89.6,2.8 89.6,-4.4 92,-4.4 92,5.6 82.5,5.6 82.5,4.1
  text "5" at 128.746,-14.121 h1.52 r90
  text "'.Pcb_File_Name_No_Path'    '.Layer_Name'     '.Print_Date'     '.Print_Time'" at 9.954,-31.338 h1.52
plane 4 (plane layer: these items are gaps in the copper):
  rectangle: 126.75,-9.25 129.25,-7.5
  rectangle: 126.75,-20 129.25,-12.75
  text "7" at 128.746,-10.621 h1.52 r90
  text "'.Pcb_File_Name_No_Path'    '.Layer_Name'    '.Print_Date'    '.Print_Time'" at 9.954,-31.338 h1.52

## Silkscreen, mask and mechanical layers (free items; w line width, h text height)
Top Overlay:
  lines w0.102: 12.15,-4.75 24,-4.75 24,4.75 12.15,4.75 12.15,-4.75
  text "10_10_2020" at 8.892,-6.946 h1.52 r90
  text "ETL_RB_v1.5" at 5.561,-10.2 h2.03 r90
  text "'.Pcb_File_Name_No_Path'    '.Layer_Name'    '.Print_Date'    '.Print_Time'" at 9.854,-31.338 h1.52
Bottom Overlay:
  text "ETL_RB_v1.5" at 5.061,10.1 h2.03 r90
  text "10_10_2020" at 8.292,6.946 h1.52 r90
  text "'.Pcb_File_Name_No_Path'    '.Layer_Name'    '.Print_Date'    '.Print_Time'" at 15.054,-30.938 h1.52
Top Paste:
  text "'.Pcb_File_Name_No_Path'    '.Layer_Name'    '.Print_Date'    '.Print_Time'" at 9.754,-31.438 h1.52
Bottom Paste:
  text "'.Pcb_File_Name_No_Path'    '.Layer_Name'    '.Print_Date'    '.Print_Time'" at 9.754,-31.692 h1.52
Top Solder:
  text "'.Pcb_File_Name_No_Path'    '.Layer_Name'    '.Print_Date'    '.Print_Time'" at 9.754,-31.438 h1.52
Bottom Solder:
  text "'.Pcb_File_Name_No_Path'    '.Layer_Name'    '.Print_Date'    '.Print_Time'" at 9.754,-31.692 h1.52
Drill Guide:
  text "'.Pcb_File_Name_No_Path'    '.Layer_Name'    '.Print_Date'    '.Print_Time'" at 9.754,-31.692 h1.52
Mechanical 1:
  the board outline again, w0.15
Mechanical 14:
  the board outline again, w0.15
  text "12X" at -17.346,-27.946 h1.52
  text "'.Pcb_File_Name_No_Path'    '.Layer_Name'    '.Print_Date'    '.Print_Time'" at 9.954,-31.292 h1.52
  text "We adopted the layer stack recommended by you. The stack file is included in the manufacturing documentation." at -16.046,-34.138 h1.52
  text "The surfatce treatment of top and bottom layers is immersion gold." at -16.346,-36.738 h1.52
  text "We have high voltage up to 1000V on some components, so please chose the solder mask material with this in mind." at -16.146,-40.038 h1.52
  text "Traces with 0.12mm width are impedance controlled signals. Please tune the width to get to 50 Ohm." at -16.346,-43.038 h1.52
Drill Drawing:
  text "'.Pcb_File_Name_No_Path'    '.Layer_Name'    '.Print_Date'    '.Print_Time'" at 9.954,-31.338 h1.52

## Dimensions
137.8,-28.25 to 125.3,28.25 on Mechanical 14
132.3,-28.25 to 130.3,23.25 on Mechanical 14
125.3,-28.25 to 130.3,-23.25 on Mechanical 14
4.6,-24 to 1.3,-27 on Mechanical 14
0,44.1 to 130.3,23.25 on Mechanical 14
0,40.8 to 125.3,28.25 on Mechanical 14
0,37.4 to 91.95,28.25 on Mechanical 14
0,35.3 to 81.95,28.25 on Mechanical 14
0,32.7 to 48.35,28.25 on Mechanical 14
0,30.028 to 38.35,28.24 on Mechanical 14
0,23.25 to 5,28.25 on Mechanical 14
